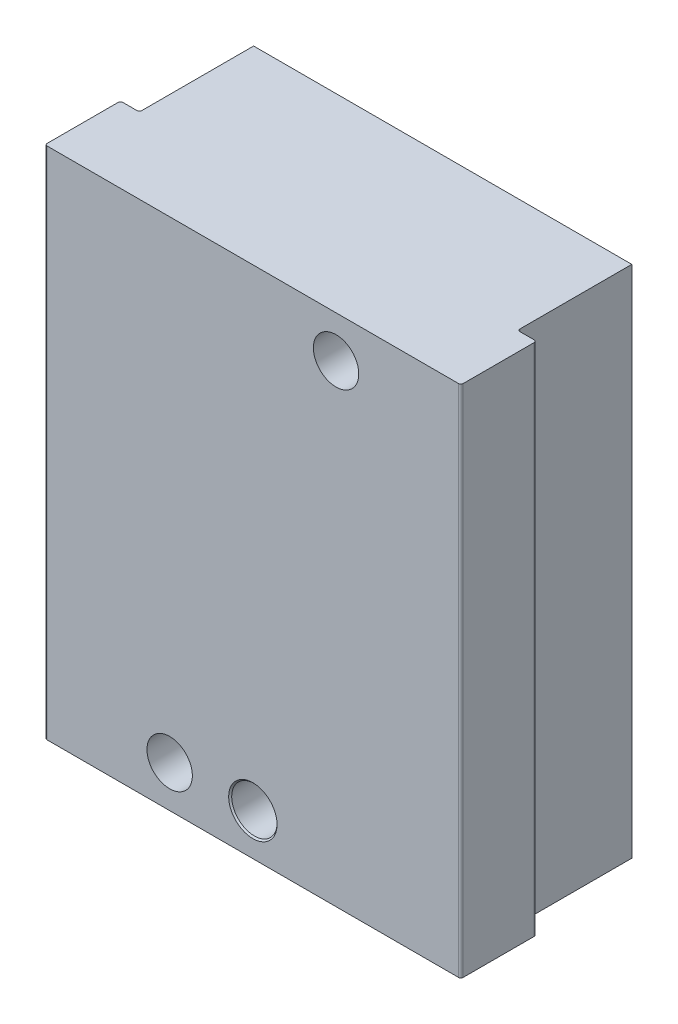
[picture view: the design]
ISO-10303-21;
HEADER;
FILE_DESCRIPTION(('STEP AP214'),'2;1');
FILE_NAME('part.step','',(''),(''),'','','');
FILE_SCHEMA(('AUTOMOTIVE_DESIGN { 1 0 10303 214 1 1 1 1 }'));
ENDSEC;
DATA;
#1=APPLICATION_CONTEXT('core data for automotive mechanical design processes');
#2=APPLICATION_PROTOCOL_DEFINITION('international standard','automotive_design',2000,#1);
#3=PRODUCT_CONTEXT('',#1,'mechanical');
#4=PRODUCT('Part','Part','',(#3));
#5=PRODUCT_RELATED_PRODUCT_CATEGORY('part','',(#4));
#6=PRODUCT_DEFINITION_FORMATION('','',#4);
#7=PRODUCT_DEFINITION_CONTEXT('part definition',#1,'design');
#8=PRODUCT_DEFINITION('design','',#6,#7);
#9=PRODUCT_DEFINITION_SHAPE('','',#8);
#10=(LENGTH_UNIT() NAMED_UNIT(*) SI_UNIT(.MILLI.,.METRE.));
#11=(NAMED_UNIT(*) PLANE_ANGLE_UNIT() SI_UNIT($,.RADIAN.));
#12=(NAMED_UNIT(*) SI_UNIT($,.STERADIAN.) SOLID_ANGLE_UNIT());
#13=UNCERTAINTY_MEASURE_WITH_UNIT(LENGTH_MEASURE(1.E-05),#10,'distance_accuracy_value','');
#14=(GEOMETRIC_REPRESENTATION_CONTEXT(3) GLOBAL_UNCERTAINTY_ASSIGNED_CONTEXT((#13)) GLOBAL_UNIT_ASSIGNED_CONTEXT((#10,
#11,#12)) REPRESENTATION_CONTEXT('',''));
#15=CARTESIAN_POINT('',(0.,0.,0.));
#16=DIRECTION('',(0.,0.,1.));
#17=DIRECTION('',(1.,0.,0.));
#18=AXIS2_PLACEMENT_3D('',#15,#16,#17);
#19=CARTESIAN_POINT('',(0.,5.5,0.));
#20=DIRECTION('',(0.,0.,-1.));
#21=DIRECTION('',(-1.,0.,0.));
#22=AXIS2_PLACEMENT_3D('',#19,#20,#21);
#23=CYLINDRICAL_SURFACE('',#22,1.5);
#24=CARTESIAN_POINT('',(0.,5.5,-25.1));
#25=DIRECTION('',(0.,0.,-1.));
#26=DIRECTION('',(-1.,0.,0.));
#27=AXIS2_PLACEMENT_3D('',#24,#25,#26);
#28=CIRCLE('',#27,1.5);
#29=CARTESIAN_POINT('',(0.70367829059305,4.17529744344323,-25.1));
#30=VERTEX_POINT('',#29);
#31=CARTESIAN_POINT('',(-0.70367829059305,6.82470255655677,-25.1));
#32=VERTEX_POINT('',#31);
#33=EDGE_CURVE('E509',#30,#32,#28,.T.);
#34=ORIENTED_EDGE('',*,*,#33,.T.);
#35=CARTESIAN_POINT('',(0.,5.5,-7.95492154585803));
#36=DIRECTION('',(-0.467333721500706,0.87977444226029,0.0871557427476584));
#37=DIRECTION('',(-0.0408864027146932,0.0769702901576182,-0.996194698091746));
#38=AXIS2_PLACEMENT_3D('',#35,#36,#37);
#39=ELLIPSE('',#38,17.2105698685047,1.5);
#40=CARTESIAN_POINT('',(0.168038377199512,6.99055798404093,-22.1));
#41=VERTEX_POINT('',#40);
#42=EDGE_CURVE('E714',#32,#41,#39,.F.);
#43=ORIENTED_EDGE('',*,*,#42,.T.);
#44=CARTESIAN_POINT('',(0.,5.5,-22.1));
#45=DIRECTION('',(0.,0.,-1.));
#46=DIRECTION('',(-1.,0.,0.));
#47=AXIS2_PLACEMENT_3D('',#44,#45,#46);
#48=CIRCLE('',#47,1.5);
#49=CARTESIAN_POINT('',(1.32913946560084,4.80473869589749,-22.1));
#50=VERTEX_POINT('',#49);
#51=EDGE_CURVE('E336',#50,#41,#48,.F.);
#52=ORIENTED_EDGE('',*,*,#51,.F.);
#53=CARTESIAN_POINT('',(0.,5.5,-7.95492154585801));
#54=DIRECTION('',(0.467333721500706,-0.87977444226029,0.0871557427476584));
#55=DIRECTION('',(0.0408864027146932,-0.0769702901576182,-0.996194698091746));
#56=AXIS2_PLACEMENT_3D('',#53,#54,#55);
#57=ELLIPSE('',#56,17.2105698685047,1.5);
#58=EDGE_CURVE('E715',#50,#30,#57,.F.);
#59=ORIENTED_EDGE('',*,*,#58,.T.);
#60=EDGE_LOOP('',(#34,#43,#52,#59));
#61=FACE_BOUND('',#60,.T.);
#62=CARTESIAN_POINT('',(0.,5.5,-10.));
#63=DIRECTION('',(0.,0.,1.));
#64=DIRECTION('',(1.,0.,0.));
#65=AXIS2_PLACEMENT_3D('',#62,#63,#64);
#66=CIRCLE('',#65,1.5);
#67=CARTESIAN_POINT('',(1.5,5.5,-10.));
#68=VERTEX_POINT('',#67);
#69=EDGE_CURVE('E506',#68,#68,#66,.F.);
#70=ORIENTED_EDGE('',*,*,#69,.F.);
#71=EDGE_LOOP('',(#70));
#72=FACE_BOUND('',#71,.T.);
#73=ADVANCED_FACE('F34',(#61,#72),#23,.F.);
#74=CARTESIAN_POINT('',(27.5,68.,-10.));
#75=DIRECTION('',(-1.,0.,0.));
#76=DIRECTION('',(0.,0.,1.));
#77=AXIS2_PLACEMENT_3D('',#74,#75,#76);
#78=PLANE('',#77);
#79=DIRECTION('',(0.,0.,-1.));
#80=VECTOR('',#79,1.);
#81=CARTESIAN_POINT('',(27.5,0.,-10.));
#82=LINE('',#81,#80);
#83=CARTESIAN_POINT('',(27.5,0.,-0.3));
#84=VERTEX_POINT('',#83);
#85=CARTESIAN_POINT('',(27.5,0.,-9.7));
#86=VERTEX_POINT('',#85);
#87=EDGE_CURVE('E604',#84,#86,#82,.T.);
#88=ORIENTED_EDGE('',*,*,#87,.T.);
#89=DIRECTION('',(0.,-1.,0.));
#90=VECTOR('',#89,1.);
#91=CARTESIAN_POINT('',(27.5,68.,-9.7));
#92=LINE('',#91,#90);
#93=CARTESIAN_POINT('',(27.5,68.,-9.7));
#94=VERTEX_POINT('',#93);
#95=EDGE_CURVE('E469',#86,#94,#92,.F.);
#96=ORIENTED_EDGE('',*,*,#95,.T.);
#97=DIRECTION('',(0.,0.,-1.));
#98=VECTOR('',#97,1.);
#99=CARTESIAN_POINT('',(27.5,68.,-10.));
#100=LINE('',#99,#98);
#101=CARTESIAN_POINT('',(27.5,68.,-0.3));
#102=VERTEX_POINT('',#101);
#103=EDGE_CURVE('E607',#102,#94,#100,.T.);
#104=ORIENTED_EDGE('',*,*,#103,.F.);
#105=DIRECTION('',(0.,-1.,0.));
#106=VECTOR('',#105,1.);
#107=CARTESIAN_POINT('',(27.5,68.,-0.3));
#108=LINE('',#107,#106);
#109=EDGE_CURVE('E473',#102,#84,#108,.T.);
#110=ORIENTED_EDGE('',*,*,#109,.T.);
#111=EDGE_LOOP('',(#88,#96,#104,#110));
#112=FACE_BOUND('',#111,.T.);
#113=ADVANCED_FACE('F377',(#112),#78,.F.);
#114=CARTESIAN_POINT('',(27.5,68.,-10.));
#115=DIRECTION('',(0.,0.,1.));
#116=DIRECTION('',(1.,0.,0.));
#117=AXIS2_PLACEMENT_3D('',#114,#115,#116);
#118=PLANE('',#117);
#119=DIRECTION('',(-1.,0.,0.));
#120=VECTOR('',#119,1.);
#121=CARTESIAN_POINT('',(27.5,68.,-10.));
#122=LINE('',#121,#120);
#123=CARTESIAN_POINT('',(27.2,68.,-10.));
#124=VERTEX_POINT('',#123);
#125=CARTESIAN_POINT('',(25.3,68.,-10.));
#126=VERTEX_POINT('',#125);
#127=EDGE_CURVE('E610',#124,#126,#122,.T.);
#128=ORIENTED_EDGE('',*,*,#127,.F.);
#129=DIRECTION('',(0.,-1.,0.));
#130=VECTOR('',#129,1.);
#131=CARTESIAN_POINT('',(27.2,68.,-10.));
#132=LINE('',#131,#130);
#133=CARTESIAN_POINT('',(27.2,0.,-10.));
#134=VERTEX_POINT('',#133);
#135=EDGE_CURVE('E656',#124,#134,#132,.T.);
#136=ORIENTED_EDGE('',*,*,#135,.T.);
#137=DIRECTION('',(-1.,0.,0.));
#138=VECTOR('',#137,1.);
#139=CARTESIAN_POINT('',(27.5,0.,-10.));
#140=LINE('',#139,#138);
#141=CARTESIAN_POINT('',(25.3,0.,-10.));
#142=VERTEX_POINT('',#141);
#143=EDGE_CURVE('E631',#134,#142,#140,.T.);
#144=ORIENTED_EDGE('',*,*,#143,.T.);
#145=DIRECTION('',(0.,-1.,0.));
#146=VECTOR('',#145,1.);
#147=CARTESIAN_POINT('',(25.3,68.,-10.));
#148=LINE('',#147,#146);
#149=EDGE_CURVE('E654',#142,#126,#148,.F.);
#150=ORIENTED_EDGE('',*,*,#149,.T.);
#151=EDGE_LOOP('',(#128,#136,#144,#150));
#152=FACE_BOUND('',#151,.T.);
#153=ADVANCED_FACE('F383',(#152),#118,.F.);
#154=CARTESIAN_POINT('',(25.,68.,-25.1));
#155=DIRECTION('',(-1.,0.,0.));
#156=DIRECTION('',(0.,0.,1.));
#157=AXIS2_PLACEMENT_3D('',#154,#155,#156);
#158=PLANE('',#157);
#159=DIRECTION('',(0.,0.,-1.));
#160=VECTOR('',#159,1.);
#161=CARTESIAN_POINT('',(25.,68.,-25.1));
#162=LINE('',#161,#160);
#163=CARTESIAN_POINT('',(25.,68.,-10.3));
#164=VERTEX_POINT('',#163);
#165=CARTESIAN_POINT('',(25.,68.,-25.1));
#166=VERTEX_POINT('',#165);
#167=EDGE_CURVE('E614',#164,#166,#162,.T.);
#168=ORIENTED_EDGE('',*,*,#167,.F.);
#169=DIRECTION('',(0.,-1.,0.));
#170=VECTOR('',#169,1.);
#171=CARTESIAN_POINT('',(25.,0.,-10.3));
#172=LINE('',#171,#170);
#173=CARTESIAN_POINT('',(25.,0.,-10.3));
#174=VERTEX_POINT('',#173);
#175=EDGE_CURVE('E480',#164,#174,#172,.T.);
#176=ORIENTED_EDGE('',*,*,#175,.T.);
#177=DIRECTION('',(0.,0.,-1.));
#178=VECTOR('',#177,1.);
#179=CARTESIAN_POINT('',(25.,0.,-25.1));
#180=LINE('',#179,#178);
#181=CARTESIAN_POINT('',(25.,0.,-25.1));
#182=VERTEX_POINT('',#181);
#183=EDGE_CURVE('E634',#174,#182,#180,.T.);
#184=ORIENTED_EDGE('',*,*,#183,.T.);
#185=DIRECTION('',(0.,-1.,0.));
#186=VECTOR('',#185,1.);
#187=CARTESIAN_POINT('',(25.,68.,-25.1));
#188=LINE('',#187,#186);
#189=EDGE_CURVE('E651',#166,#182,#188,.T.);
#190=ORIENTED_EDGE('',*,*,#189,.F.);
#191=EDGE_LOOP('',(#168,#176,#184,#190));
#192=FACE_BOUND('',#191,.T.);
#193=ADVANCED_FACE('F429',(#192),#158,.F.);
#194=CARTESIAN_POINT('',(-25.,68.,-25.1));
#195=DIRECTION('',(0.,0.,1.));
#196=DIRECTION('',(1.,0.,0.));
#197=AXIS2_PLACEMENT_3D('',#194,#195,#196);
#198=PLANE('',#197);
#199=DIRECTION('',(-0.469118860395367,0.883135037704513,0.));
#200=VECTOR('',#199,1.);
#201=CARTESIAN_POINT('',(-26.7317629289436,67.0800923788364,-25.1));
#202=LINE('',#201,#200);
#203=CARTESIAN_POINT('',(4.42894667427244,8.41880890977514,-25.1));
#204=VERTEX_POINT('',#203);
#205=CARTESIAN_POINT('',(3.71148847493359,9.76945269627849,-25.1));
#206=VERTEX_POINT('',#205);
#207=EDGE_CURVE('E334',#204,#206,#202,.T.);
#208=ORIENTED_EDGE('',*,*,#207,.F.);
#209=DIRECTION('',(0.883135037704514,0.469118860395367,0.));
#210=VECTOR('',#209,1.);
#211=CARTESIAN_POINT('',(4.8705141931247,8.65336833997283,-25.1));
#212=LINE('',#211,#210);
#213=CARTESIAN_POINT('',(3.91161814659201,8.14400544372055,-25.1));
#214=VERTEX_POINT('',#213);
#215=EDGE_CURVE('E326',#214,#204,#212,.T.);
#216=ORIENTED_EDGE('',*,*,#215,.F.);
#217=CARTESIAN_POINT('',(2.8972360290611,7.03900367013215,-25.1));
#218=DIRECTION('',(0.,0.,-1.));
#219=DIRECTION('',(-1.,0.,0.));
#220=AXIS2_PLACEMENT_3D('',#217,#218,#219);
#221=CIRCLE('',#220,1.5);
#222=CARTESIAN_POINT('',(2.19355773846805,8.36370622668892,-25.1));
#223=VERTEX_POINT('',#222);
#224=EDGE_CURVE('E723',#223,#214,#221,.T.);
#225=ORIENTED_EDGE('',*,*,#224,.F.);
#226=DIRECTION('',(0.883135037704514,0.469118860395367,0.));
#227=VECTOR('',#226,1.);
#228=CARTESIAN_POINT('',(2.19355773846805,8.36370622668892,-25.1));
#229=LINE('',#228,#227);
#230=EDGE_CURVE('E720',#32,#223,#229,.T.);
#231=ORIENTED_EDGE('',*,*,#230,.F.);
#232=ORIENTED_EDGE('',*,*,#33,.F.);
#233=DIRECTION('',(-0.883135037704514,-0.469118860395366,0.));
#234=VECTOR('',#233,1.);
#235=CARTESIAN_POINT('',(3.60091431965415,5.71430111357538,-25.1));
#236=LINE('',#235,#234);
#237=CARTESIAN_POINT('',(3.60091431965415,5.71430111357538,-25.1));
#238=VERTEX_POINT('',#237);
#239=EDGE_CURVE('E717',#238,#30,#236,.T.);
#240=ORIENTED_EDGE('',*,*,#239,.F.);
#241=CARTESIAN_POINT('',(4.38073700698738,7.26087040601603,-25.1));
#242=VERTEX_POINT('',#241);
#243=EDGE_CURVE('E62',#242,#238,#221,.T.);
#244=ORIENTED_EDGE('',*,*,#243,.F.);
#245=DIRECTION('',(-0.883135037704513,-0.469118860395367,0.));
#246=VECTOR('',#245,1.);
#247=CARTESIAN_POINT('',(5.33963305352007,7.77023330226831,-25.1));
#248=LINE('',#247,#246);
#249=CARTESIAN_POINT('',(4.89806553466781,7.53567387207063,-25.1));
#250=VERTEX_POINT('',#249);
#251=EDGE_CURVE('E311',#250,#242,#248,.T.);
#252=ORIENTED_EDGE('',*,*,#251,.F.);
#253=CARTESIAN_POINT('',(6.16552373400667,5.14963306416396,-25.1));
#254=VERTEX_POINT('',#253);
#255=EDGE_CURVE('E324',#254,#250,#202,.T.);
#256=ORIENTED_EDGE('',*,*,#255,.F.);
#257=CARTESIAN_POINT('',(7.97595056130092,6.11132672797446,-25.1));
#258=DIRECTION('',(0.,0.,1.));
#259=DIRECTION('',(1.,0.,0.));
#260=AXIS2_PLACEMENT_3D('',#257,#258,#259);
#261=CIRCLE('',#260,2.05);
#262=CARTESIAN_POINT('',(8.93764422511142,4.30089990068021,-25.1));
#263=VERTEX_POINT('',#262);
#264=EDGE_CURVE('E333',#254,#263,#261,.T.);
#265=ORIENTED_EDGE('',*,*,#264,.T.);
#266=DIRECTION('',(-0.883135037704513,-0.469118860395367,0.));
#267=VECTOR('',#266,1.);
#268=CARTESIAN_POINT('',(8.85898032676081,4.25911385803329,-25.1));
#269=LINE('',#268,#267);
#270=CARTESIAN_POINT('',(17.9897783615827,9.10936821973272,-25.1));
#271=VERTEX_POINT('',#270);
#272=EDGE_CURVE('E338',#271,#263,#269,.T.);
#273=ORIENTED_EDGE('',*,*,#272,.F.);
#274=CARTESIAN_POINT('',(17.0280846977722,10.919795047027,-25.1));
#275=DIRECTION('',(0.,0.,1.));
#276=DIRECTION('',(1.,0.,0.));
#277=AXIS2_PLACEMENT_3D('',#274,#275,#276);
#278=CIRCLE('',#277,2.05);
#279=CARTESIAN_POINT('',(18.8385115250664,11.8814887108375,-25.1));
#280=VERTEX_POINT('',#279);
#281=EDGE_CURVE('E552',#271,#280,#278,.T.);
#282=ORIENTED_EDGE('',*,*,#281,.T.);
#283=DIRECTION('',(0.469118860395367,-0.883135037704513,0.));
#284=VECTOR('',#283,1.);
#285=CARTESIAN_POINT('',(-14.0587751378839,73.8119480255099,-25.1));
#286=LINE('',#285,#284);
#287=CARTESIAN_POINT('',(16.3844762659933,16.501308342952,-25.1));
#288=VERTEX_POINT('',#287);
#289=EDGE_CURVE('E550',#288,#280,#286,.T.);
#290=ORIENTED_EDGE('',*,*,#289,.F.);
#291=CARTESIAN_POINT('',(14.5740494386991,15.5396146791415,-25.1));
#292=DIRECTION('',(0.,0.,1.));
#293=DIRECTION('',(1.,0.,0.));
#294=AXIS2_PLACEMENT_3D('',#291,#292,#293);
#295=CIRCLE('',#294,2.05);
#296=CARTESIAN_POINT('',(15.1545615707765,17.5057036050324,-25.1));
#297=VERTEX_POINT('',#296);
#298=EDGE_CURVE('E545',#288,#297,#295,.T.);
#299=ORIENTED_EDGE('',*,*,#298,.T.);
#300=CARTESIAN_POINT('',(17.4766100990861,25.3700593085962,-25.1));
#301=DIRECTION('',(0.,0.,1.));
#302=DIRECTION('',(1.,0.,0.));
#303=AXIS2_PLACEMENT_3D('',#300,#301,#302);
#304=CIRCLE('',#303,8.2);
#305=CARTESIAN_POINT('',(10.234902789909,21.5232846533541,-25.1));
#306=VERTEX_POINT('',#305);
#307=EDGE_CURVE('E539',#306,#297,#304,.T.);
#308=ORIENTED_EDGE('',*,*,#307,.F.);
#309=DIRECTION('',(0.469118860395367,-0.883135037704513,0.));
#310=VECTOR('',#309,1.);
#311=CARTESIAN_POINT('',(-16.7744153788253,72.3694075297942,-25.1));
#312=LINE('',#311,#310);
#313=CARTESIAN_POINT('',(-2.99319548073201,46.4257092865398,-25.1));
#314=VERTEX_POINT('',#313);
#315=EDGE_CURVE('E534',#314,#306,#312,.T.);
#316=ORIENTED_EDGE('',*,*,#315,.F.);
#317=CARTESIAN_POINT('',(4.248511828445,50.2724839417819,-25.1));
#318=DIRECTION('',(0.,0.,1.));
#319=DIRECTION('',(1.,0.,0.));
#320=AXIS2_PLACEMENT_3D('',#317,#318,#319);
#321=CIRCLE('',#320,8.2);
#322=CARTESIAN_POINT('',(-3.56782987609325,52.7513551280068,-25.1));
#323=VERTEX_POINT('',#322);
#324=EDGE_CURVE('E530',#323,#314,#321,.T.);
#325=ORIENTED_EDGE('',*,*,#324,.F.);
#326=CARTESIAN_POINT('',(-5.52191530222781,53.371072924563,-25.1));
#327=DIRECTION('',(0.,0.,1.));
#328=DIRECTION('',(1.,0.,0.));
#329=AXIS2_PLACEMENT_3D('',#326,#327,#328);
#330=CIRCLE('',#329,2.05);
#331=CARTESIAN_POINT('',(-3.71148847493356,54.3327665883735,-25.1));
#332=VERTEX_POINT('',#331);
#333=EDGE_CURVE('E524',#323,#332,#330,.T.);
#334=ORIENTED_EDGE('',*,*,#333,.T.);
#335=DIRECTION('',(0.469118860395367,-0.883135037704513,0.));
#336=VECTOR('',#335,1.);
#337=CARTESIAN_POINT('',(-14.0587751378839,73.8119480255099,-25.1));
#338=LINE('',#337,#336);
#339=CARTESIAN_POINT('',(-6.16552373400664,58.952586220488,-25.1));
#340=VERTEX_POINT('',#339);
#341=EDGE_CURVE('E522',#340,#332,#338,.T.);
#342=ORIENTED_EDGE('',*,*,#341,.F.);
#343=CARTESIAN_POINT('',(-7.9759505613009,57.9908925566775,-25.1));
#344=DIRECTION('',(0.,0.,1.));
#345=DIRECTION('',(1.,0.,0.));
#346=AXIS2_PLACEMENT_3D('',#343,#344,#345);
#347=CIRCLE('',#346,2.05);
#348=CARTESIAN_POINT('',(-8.9376442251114,59.8013193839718,-25.1));
#349=VERTEX_POINT('',#348);
#350=EDGE_CURVE('E516',#340,#349,#347,.T.);
#351=ORIENTED_EDGE('',*,*,#350,.T.);
#352=DIRECTION('',(0.883135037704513,0.469118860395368,0.));
#353=VECTOR('',#352,1.);
#354=CARTESIAN_POINT('',(-18.0684422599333,54.9510650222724,-25.1));
#355=LINE('',#354,#353);
#356=CARTESIAN_POINT('',(-17.9897783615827,54.9928510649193,-25.1));
#357=VERTEX_POINT('',#356);
#358=EDGE_CURVE('E519',#357,#349,#355,.T.);
#359=ORIENTED_EDGE('',*,*,#358,.F.);
#360=CARTESIAN_POINT('',(-17.0280846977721,53.182424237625,-25.1));
#361=DIRECTION('',(0.,0.,1.));
#362=DIRECTION('',(1.,0.,0.));
#363=AXIS2_PLACEMENT_3D('',#360,#361,#362);
#364=CIRCLE('',#363,2.05);
#365=CARTESIAN_POINT('',(-18.8385115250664,52.2207305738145,-25.1));
#366=VERTEX_POINT('',#365);
#367=EDGE_CURVE('E527',#357,#366,#364,.T.);
#368=ORIENTED_EDGE('',*,*,#367,.T.);
#369=DIRECTION('',(-0.469118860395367,0.883135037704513,0.));
#370=VECTOR('',#369,1.);
#371=CARTESIAN_POINT('',(-26.7317629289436,67.0800923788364,-25.1));
#372=LINE('',#371,#370);
#373=CARTESIAN_POINT('',(-16.3844762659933,47.6009109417,-25.1));
#374=VERTEX_POINT('',#373);
#375=EDGE_CURVE('E532',#374,#366,#372,.T.);
#376=ORIENTED_EDGE('',*,*,#375,.F.);
#377=CARTESIAN_POINT('',(-14.5740494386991,48.5626046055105,-25.1));
#378=DIRECTION('',(0.,0.,1.));
#379=DIRECTION('',(1.,0.,0.));
#380=AXIS2_PLACEMENT_3D('',#377,#378,#379);
#381=CIRCLE('',#380,2.05);
#382=CARTESIAN_POINT('',(-15.1545615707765,46.5965156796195,-25.1));
#383=VERTEX_POINT('',#382);
#384=EDGE_CURVE('E536',#374,#383,#381,.T.);
#385=ORIENTED_EDGE('',*,*,#384,.T.);
#386=CARTESIAN_POINT('',(-17.476610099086,38.7321599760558,-25.1));
#387=DIRECTION('',(0.,0.,1.));
#388=DIRECTION('',(1.,0.,0.));
#389=AXIS2_PLACEMENT_3D('',#386,#387,#388);
#390=CIRCLE('',#389,8.2);
#391=CARTESIAN_POINT('',(-10.234902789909,42.5789346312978,-25.1));
#392=VERTEX_POINT('',#391);
#393=EDGE_CURVE('E541',#392,#383,#390,.T.);
#394=ORIENTED_EDGE('',*,*,#393,.F.);
#395=DIRECTION('',(-0.469118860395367,0.883135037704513,0.));
#396=VECTOR('',#395,1.);
#397=CARTESIAN_POINT('',(-24.0161226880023,68.5226328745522,-25.1));
#398=LINE('',#397,#396);
#399=CARTESIAN_POINT('',(2.99319548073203,17.6765099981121,-25.1));
#400=VERTEX_POINT('',#399);
#401=EDGE_CURVE('E543',#400,#392,#398,.T.);
#402=ORIENTED_EDGE('',*,*,#401,.F.);
#403=CARTESIAN_POINT('',(-4.24851182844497,13.8297353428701,-25.1));
#404=DIRECTION('',(0.,0.,1.));
#405=DIRECTION('',(1.,0.,0.));
#406=AXIS2_PLACEMENT_3D('',#403,#404,#405);
#407=CIRCLE('',#406,8.2);
#408=CARTESIAN_POINT('',(3.56782987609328,11.3508641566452,-25.1));
#409=VERTEX_POINT('',#408);
#410=EDGE_CURVE('E548',#409,#400,#407,.T.);
#411=ORIENTED_EDGE('',*,*,#410,.F.);
#412=CARTESIAN_POINT('',(5.52191530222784,10.731146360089,-25.1));
#413=DIRECTION('',(0.,0.,1.));
#414=DIRECTION('',(1.,0.,0.));
#415=AXIS2_PLACEMENT_3D('',#412,#413,#414);
#416=CIRCLE('',#415,2.05);
#417=EDGE_CURVE('E554',#409,#206,#416,.T.);
#418=ORIENTED_EDGE('',*,*,#417,.T.);
#419=EDGE_LOOP('',(#208,#216,#225,#231,#232,#240,#244,#252,#256,#265,#273,#282,#290,#299,#308,
#316,#325,#334,#342,#351,#359,#368,#376,#385,#394,#402,#411,#418));
#420=FACE_BOUND('',#419,.T.);
#421=CARTESIAN_POINT('',(-11.,5.5,-25.1));
#422=DIRECTION('',(0.,0.,-1.));
#423=DIRECTION('',(-1.,0.,0.));
#424=AXIS2_PLACEMENT_3D('',#421,#422,#423);
#425=CIRCLE('',#424,3.);
#426=CARTESIAN_POINT('',(-14.,5.5,-25.1));
#427=VERTEX_POINT('',#426);
#428=EDGE_CURVE('E594',#427,#427,#425,.T.);
#429=ORIENTED_EDGE('',*,*,#428,.F.);
#430=EDGE_LOOP('',(#429));
#431=FACE_BOUND('',#430,.T.);
#432=CARTESIAN_POINT('',(11.,62.5,-25.1));
#433=DIRECTION('',(0.,0.,-1.));
#434=DIRECTION('',(-1.,0.,0.));
#435=AXIS2_PLACEMENT_3D('',#432,#433,#434);
#436=CIRCLE('',#435,3.);
#437=CARTESIAN_POINT('',(8.,62.5,-25.1));
#438=VERTEX_POINT('',#437);
#439=EDGE_CURVE('E598',#438,#438,#436,.T.);
#440=ORIENTED_EDGE('',*,*,#439,.F.);
#441=EDGE_LOOP('',(#440));
#442=FACE_BOUND('',#441,.T.);
#443=DIRECTION('',(-1.,0.,0.));
#444=VECTOR('',#443,1.);
#445=CARTESIAN_POINT('',(-25.,0.,-25.1));
#446=LINE('',#445,#444);
#447=CARTESIAN_POINT('',(-25.,0.,-25.1));
#448=VERTEX_POINT('',#447);
#449=EDGE_CURVE('E636',#182,#448,#446,.T.);
#450=ORIENTED_EDGE('',*,*,#449,.T.);
#451=DIRECTION('',(0.,-1.,0.));
#452=VECTOR('',#451,1.);
#453=CARTESIAN_POINT('',(-25.,68.,-25.1));
#454=LINE('',#453,#452);
#455=CARTESIAN_POINT('',(-25.,68.,-25.1));
#456=VERTEX_POINT('',#455);
#457=EDGE_CURVE('E628',#456,#448,#454,.T.);
#458=ORIENTED_EDGE('',*,*,#457,.F.);
#459=DIRECTION('',(-1.,0.,0.));
#460=VECTOR('',#459,1.);
#461=CARTESIAN_POINT('',(-25.,68.,-25.1));
#462=LINE('',#461,#460);
#463=EDGE_CURVE('E616',#166,#456,#462,.T.);
#464=ORIENTED_EDGE('',*,*,#463,.F.);
#465=ORIENTED_EDGE('',*,*,#189,.T.);
#466=EDGE_LOOP('',(#450,#458,#464,#465));
#467=FACE_BOUND('',#466,.T.);
#468=ADVANCED_FACE('F321',(#420,#431,#442,#467),#198,.F.);
#469=CARTESIAN_POINT('',(-25.,68.,-25.1));
#470=DIRECTION('',(1.,0.,0.));
#471=DIRECTION('',(0.,0.,-1.));
#472=AXIS2_PLACEMENT_3D('',#469,#470,#471);
#473=PLANE('',#472);
#474=DIRECTION('',(0.,0.,1.));
#475=VECTOR('',#474,1.);
#476=CARTESIAN_POINT('',(-25.,0.,-25.1));
#477=LINE('',#476,#475);
#478=CARTESIAN_POINT('',(-25.,0.,-10.3));
#479=VERTEX_POINT('',#478);
#480=EDGE_CURVE('E638',#448,#479,#477,.T.);
#481=ORIENTED_EDGE('',*,*,#480,.T.);
#482=DIRECTION('',(0.,-1.,0.));
#483=VECTOR('',#482,1.);
#484=CARTESIAN_POINT('',(-25.,68.,-10.3));
#485=LINE('',#484,#483);
#486=CARTESIAN_POINT('',(-25.,68.,-10.3));
#487=VERTEX_POINT('',#486);
#488=EDGE_CURVE('E488',#479,#487,#485,.F.);
#489=ORIENTED_EDGE('',*,*,#488,.T.);
#490=DIRECTION('',(0.,0.,1.));
#491=VECTOR('',#490,1.);
#492=CARTESIAN_POINT('',(-25.,68.,-25.1));
#493=LINE('',#492,#491);
#494=EDGE_CURVE('E618',#456,#487,#493,.T.);
#495=ORIENTED_EDGE('',*,*,#494,.F.);
#496=ORIENTED_EDGE('',*,*,#457,.T.);
#497=EDGE_LOOP('',(#481,#489,#495,#496));
#498=FACE_BOUND('',#497,.T.);
#499=ADVANCED_FACE('F422',(#498),#473,.F.);
#500=CARTESIAN_POINT('',(-27.5,68.,-10.));
#501=DIRECTION('',(0.,0.,1.));
#502=DIRECTION('',(1.,0.,0.));
#503=AXIS2_PLACEMENT_3D('',#500,#501,#502);
#504=PLANE('',#503);
#505=DIRECTION('',(-1.,0.,0.));
#506=VECTOR('',#505,1.);
#507=CARTESIAN_POINT('',(-27.5,68.,-10.));
#508=LINE('',#507,#506);
#509=CARTESIAN_POINT('',(-25.3,68.,-10.));
#510=VERTEX_POINT('',#509);
#511=CARTESIAN_POINT('',(-27.2,68.,-10.));
#512=VERTEX_POINT('',#511);
#513=EDGE_CURVE('E621',#510,#512,#508,.T.);
#514=ORIENTED_EDGE('',*,*,#513,.F.);
#515=DIRECTION('',(0.,-1.,0.));
#516=VECTOR('',#515,1.);
#517=CARTESIAN_POINT('',(-25.3,0.,-10.));
#518=LINE('',#517,#516);
#519=CARTESIAN_POINT('',(-25.3,0.,-10.));
#520=VERTEX_POINT('',#519);
#521=EDGE_CURVE('E485',#510,#520,#518,.T.);
#522=ORIENTED_EDGE('',*,*,#521,.T.);
#523=DIRECTION('',(-1.,0.,0.));
#524=VECTOR('',#523,1.);
#525=CARTESIAN_POINT('',(-27.5,0.,-10.));
#526=LINE('',#525,#524);
#527=CARTESIAN_POINT('',(-27.2,0.,-10.));
#528=VERTEX_POINT('',#527);
#529=EDGE_CURVE('E641',#520,#528,#526,.T.);
#530=ORIENTED_EDGE('',*,*,#529,.T.);
#531=DIRECTION('',(0.,-1.,0.));
#532=VECTOR('',#531,1.);
#533=CARTESIAN_POINT('',(-27.2,68.,-10.));
#534=LINE('',#533,#532);
#535=EDGE_CURVE('E483',#528,#512,#534,.F.);
#536=ORIENTED_EDGE('',*,*,#535,.T.);
#537=EDGE_LOOP('',(#514,#522,#530,#536));
#538=FACE_BOUND('',#537,.T.);
#539=ADVANCED_FACE('F418',(#538),#504,.F.);
#540=CARTESIAN_POINT('',(-27.5,68.,-10.));
#541=DIRECTION('',(1.,0.,0.));
#542=DIRECTION('',(0.,0.,-1.));
#543=AXIS2_PLACEMENT_3D('',#540,#541,#542);
#544=PLANE('',#543);
#545=DIRECTION('',(0.,0.,1.));
#546=VECTOR('',#545,1.);
#547=CARTESIAN_POINT('',(-27.5,68.,-10.));
#548=LINE('',#547,#546);
#549=CARTESIAN_POINT('',(-27.5,68.,-9.7));
#550=VERTEX_POINT('',#549);
#551=CARTESIAN_POINT('',(-27.5,68.,-0.3));
#552=VERTEX_POINT('',#551);
#553=EDGE_CURVE('E624',#550,#552,#548,.T.);
#554=ORIENTED_EDGE('',*,*,#553,.F.);
#555=DIRECTION('',(0.,-1.,0.));
#556=VECTOR('',#555,1.);
#557=CARTESIAN_POINT('',(-27.5,68.,-9.7));
#558=LINE('',#557,#556);
#559=CARTESIAN_POINT('',(-27.5,0.,-9.7));
#560=VERTEX_POINT('',#559);
#561=EDGE_CURVE('E491',#550,#560,#558,.T.);
#562=ORIENTED_EDGE('',*,*,#561,.T.);
#563=DIRECTION('',(0.,0.,1.));
#564=VECTOR('',#563,1.);
#565=CARTESIAN_POINT('',(-27.5,0.,-10.));
#566=LINE('',#565,#564);
#567=CARTESIAN_POINT('',(-27.5,0.,-0.3));
#568=VERTEX_POINT('',#567);
#569=EDGE_CURVE('E644',#560,#568,#566,.T.);
#570=ORIENTED_EDGE('',*,*,#569,.T.);
#571=DIRECTION('',(0.,-1.,0.));
#572=VECTOR('',#571,1.);
#573=CARTESIAN_POINT('',(-27.5,68.,-0.3));
#574=LINE('',#573,#572);
#575=EDGE_CURVE('E462',#568,#552,#574,.F.);
#576=ORIENTED_EDGE('',*,*,#575,.T.);
#577=EDGE_LOOP('',(#554,#562,#570,#576));
#578=FACE_BOUND('',#577,.T.);
#579=ADVANCED_FACE('F414',(#578),#544,.F.);
#580=CARTESIAN_POINT('',(-27.5,68.,0.));
#581=DIRECTION('',(0.,0.,-1.));
#582=DIRECTION('',(-1.,0.,0.));
#583=AXIS2_PLACEMENT_3D('',#580,#581,#582);
#584=PLANE('',#583);
#585=CARTESIAN_POINT('',(0.,5.5,0.));
#586=DIRECTION('',(0.,0.,-1.));
#587=DIRECTION('',(-1.,0.,0.));
#588=AXIS2_PLACEMENT_3D('',#585,#586,#587);
#589=CIRCLE('',#588,3.2);
#590=CARTESIAN_POINT('',(-3.2,5.5,0.));
#591=VERTEX_POINT('',#590);
#592=EDGE_CURVE('E513',#591,#591,#589,.T.);
#593=ORIENTED_EDGE('',*,*,#592,.T.);
#594=EDGE_LOOP('',(#593));
#595=FACE_BOUND('',#594,.T.);
#596=CARTESIAN_POINT('',(-11.,5.5,0.));
#597=DIRECTION('',(0.,0.,-1.));
#598=DIRECTION('',(-1.,0.,0.));
#599=AXIS2_PLACEMENT_3D('',#596,#597,#598);
#600=CIRCLE('',#599,3.);
#601=CARTESIAN_POINT('',(-14.,5.5,0.));
#602=VERTEX_POINT('',#601);
#603=EDGE_CURVE('E595',#602,#602,#600,.T.);
#604=ORIENTED_EDGE('',*,*,#603,.T.);
#605=EDGE_LOOP('',(#604));
#606=FACE_BOUND('',#605,.T.);
#607=CARTESIAN_POINT('',(11.,62.5,0.));
#608=DIRECTION('',(0.,0.,-1.));
#609=DIRECTION('',(-1.,0.,0.));
#610=AXIS2_PLACEMENT_3D('',#607,#608,#609);
#611=CIRCLE('',#610,3.);
#612=CARTESIAN_POINT('',(8.,62.5,0.));
#613=VERTEX_POINT('',#612);
#614=EDGE_CURVE('E601',#613,#613,#611,.T.);
#615=ORIENTED_EDGE('',*,*,#614,.T.);
#616=EDGE_LOOP('',(#615));
#617=FACE_BOUND('',#616,.T.);
#618=DIRECTION('',(1.,0.,0.));
#619=VECTOR('',#618,1.);
#620=CARTESIAN_POINT('',(-27.5,0.,0.));
#621=LINE('',#620,#619);
#622=CARTESIAN_POINT('',(-27.2,0.,0.));
#623=VERTEX_POINT('',#622);
#624=CARTESIAN_POINT('',(27.2,0.,0.));
#625=VERTEX_POINT('',#624);
#626=EDGE_CURVE('E611',#623,#625,#621,.T.);
#627=ORIENTED_EDGE('',*,*,#626,.T.);
#628=DIRECTION('',(0.,-1.,0.));
#629=VECTOR('',#628,1.);
#630=CARTESIAN_POINT('',(27.2,68.,0.));
#631=LINE('',#630,#629);
#632=CARTESIAN_POINT('',(27.2,68.,0.));
#633=VERTEX_POINT('',#632);
#634=EDGE_CURVE('E495',#625,#633,#631,.F.);
#635=ORIENTED_EDGE('',*,*,#634,.T.);
#636=DIRECTION('',(1.,0.,0.));
#637=VECTOR('',#636,1.);
#638=CARTESIAN_POINT('',(-27.5,68.,0.));
#639=LINE('',#638,#637);
#640=CARTESIAN_POINT('',(-27.2,68.,0.));
#641=VERTEX_POINT('',#640);
#642=EDGE_CURVE('E626',#641,#633,#639,.T.);
#643=ORIENTED_EDGE('',*,*,#642,.F.);
#644=DIRECTION('',(0.,-1.,0.));
#645=VECTOR('',#644,1.);
#646=CARTESIAN_POINT('',(-27.2,68.,0.));
#647=LINE('',#646,#645);
#648=EDGE_CURVE('E464',#641,#623,#647,.T.);
#649=ORIENTED_EDGE('',*,*,#648,.T.);
#650=EDGE_LOOP('',(#627,#635,#643,#649));
#651=FACE_BOUND('',#650,.T.);
#652=ADVANCED_FACE('F406',(#595,#606,#617,#651),#584,.F.);
#653=CARTESIAN_POINT('',(0.,68.,0.));
#654=DIRECTION('',(0.,1.,0.));
#655=DIRECTION('',(0.,0.,1.));
#656=AXIS2_PLACEMENT_3D('',#653,#654,#655);
#657=PLANE('',#656);
#658=ORIENTED_EDGE('',*,*,#103,.T.);
#659=CARTESIAN_POINT('',(27.2,68.,-9.7));
#660=DIRECTION('',(0.,1.,0.));
#661=DIRECTION('',(0.,0.,1.));
#662=AXIS2_PLACEMENT_3D('',#659,#660,#661);
#663=CIRCLE('',#662,0.3);
#664=EDGE_CURVE('E478',#94,#124,#663,.T.);
#665=ORIENTED_EDGE('',*,*,#664,.T.);
#666=ORIENTED_EDGE('',*,*,#127,.T.);
#667=CARTESIAN_POINT('',(25.3,68.,-10.3));
#668=DIRECTION('',(0.,1.,0.));
#669=DIRECTION('',(0.,0.,1.));
#670=AXIS2_PLACEMENT_3D('',#667,#668,#669);
#671=CIRCLE('',#670,0.3);
#672=EDGE_CURVE('E499',#126,#164,#671,.F.);
#673=ORIENTED_EDGE('',*,*,#672,.T.);
#674=ORIENTED_EDGE('',*,*,#167,.T.);
#675=ORIENTED_EDGE('',*,*,#463,.T.);
#676=ORIENTED_EDGE('',*,*,#494,.T.);
#677=CARTESIAN_POINT('',(-25.3,68.,-10.3));
#678=DIRECTION('',(0.,1.,0.));
#679=DIRECTION('',(0.,0.,1.));
#680=AXIS2_PLACEMENT_3D('',#677,#678,#679);
#681=CIRCLE('',#680,0.3);
#682=EDGE_CURVE('E503',#487,#510,#681,.F.);
#683=ORIENTED_EDGE('',*,*,#682,.T.);
#684=ORIENTED_EDGE('',*,*,#513,.T.);
#685=CARTESIAN_POINT('',(-27.2,68.,-9.7));
#686=DIRECTION('',(0.,1.,0.));
#687=DIRECTION('',(0.,0.,1.));
#688=AXIS2_PLACEMENT_3D('',#685,#686,#687);
#689=CIRCLE('',#688,0.3);
#690=EDGE_CURVE('E471',#512,#550,#689,.T.);
#691=ORIENTED_EDGE('',*,*,#690,.T.);
#692=ORIENTED_EDGE('',*,*,#553,.T.);
#693=CARTESIAN_POINT('',(-27.2,68.,-0.3));
#694=DIRECTION('',(0.,1.,0.));
#695=DIRECTION('',(0.,0.,1.));
#696=AXIS2_PLACEMENT_3D('',#693,#694,#695);
#697=CIRCLE('',#696,0.3);
#698=EDGE_CURVE('E461',#552,#641,#697,.T.);
#699=ORIENTED_EDGE('',*,*,#698,.T.);
#700=ORIENTED_EDGE('',*,*,#642,.T.);
#701=CARTESIAN_POINT('',(27.2,68.,-0.3));
#702=DIRECTION('',(0.,1.,0.));
#703=DIRECTION('',(0.,0.,1.));
#704=AXIS2_PLACEMENT_3D('',#701,#702,#703);
#705=CIRCLE('',#704,0.3);
#706=EDGE_CURVE('E468',#633,#102,#705,.T.);
#707=ORIENTED_EDGE('',*,*,#706,.T.);
#708=EDGE_LOOP('',(#658,#665,#666,#673,#674,#675,#676,#683,#684,#691,#692,#699,#700,#707));
#709=FACE_BOUND('',#708,.T.);
#710=ADVANCED_FACE('F402',(#709),#657,.T.);
#711=CARTESIAN_POINT('',(0.,0.,0.));
#712=DIRECTION('',(0.,1.,0.));
#713=DIRECTION('',(0.,0.,1.));
#714=AXIS2_PLACEMENT_3D('',#711,#712,#713);
#715=PLANE('',#714);
#716=ORIENTED_EDGE('',*,*,#143,.F.);
#717=CARTESIAN_POINT('',(27.2,0.,-9.7));
#718=DIRECTION('',(0.,1.,0.));
#719=DIRECTION('',(0.,0.,1.));
#720=AXIS2_PLACEMENT_3D('',#717,#718,#719);
#721=CIRCLE('',#720,0.3);
#722=EDGE_CURVE('E665',#134,#86,#721,.F.);
#723=ORIENTED_EDGE('',*,*,#722,.T.);
#724=ORIENTED_EDGE('',*,*,#87,.F.);
#725=CARTESIAN_POINT('',(27.2,0.,-0.3));
#726=DIRECTION('',(0.,1.,0.));
#727=DIRECTION('',(0.,0.,1.));
#728=AXIS2_PLACEMENT_3D('',#725,#726,#727);
#729=CIRCLE('',#728,0.3);
#730=EDGE_CURVE('E661',#84,#625,#729,.F.);
#731=ORIENTED_EDGE('',*,*,#730,.T.);
#732=ORIENTED_EDGE('',*,*,#626,.F.);
#733=CARTESIAN_POINT('',(-27.2,0.,-0.3));
#734=DIRECTION('',(0.,1.,0.));
#735=DIRECTION('',(0.,0.,1.));
#736=AXIS2_PLACEMENT_3D('',#733,#734,#735);
#737=CIRCLE('',#736,0.3);
#738=EDGE_CURVE('E659',#623,#568,#737,.F.);
#739=ORIENTED_EDGE('',*,*,#738,.T.);
#740=ORIENTED_EDGE('',*,*,#569,.F.);
#741=CARTESIAN_POINT('',(-27.2,0.,-9.7));
#742=DIRECTION('',(0.,1.,0.));
#743=DIRECTION('',(0.,0.,1.));
#744=AXIS2_PLACEMENT_3D('',#741,#742,#743);
#745=CIRCLE('',#744,0.3);
#746=EDGE_CURVE('E663',#560,#528,#745,.F.);
#747=ORIENTED_EDGE('',*,*,#746,.T.);
#748=ORIENTED_EDGE('',*,*,#529,.F.);
#749=CARTESIAN_POINT('',(-25.3,0.,-10.3));
#750=DIRECTION('',(0.,1.,0.));
#751=DIRECTION('',(0.,0.,1.));
#752=AXIS2_PLACEMENT_3D('',#749,#750,#751);
#753=CIRCLE('',#752,0.3);
#754=EDGE_CURVE('E501',#520,#479,#753,.T.);
#755=ORIENTED_EDGE('',*,*,#754,.T.);
#756=ORIENTED_EDGE('',*,*,#480,.F.);
#757=ORIENTED_EDGE('',*,*,#449,.F.);
#758=ORIENTED_EDGE('',*,*,#183,.F.);
#759=CARTESIAN_POINT('',(25.3,0.,-10.3));
#760=DIRECTION('',(0.,1.,0.));
#761=DIRECTION('',(0.,0.,1.));
#762=AXIS2_PLACEMENT_3D('',#759,#760,#761);
#763=CIRCLE('',#762,0.3);
#764=EDGE_CURVE('E497',#174,#142,#763,.T.);
#765=ORIENTED_EDGE('',*,*,#764,.T.);
#766=EDGE_LOOP('',(#716,#723,#724,#731,#732,#739,#740,#747,#748,#755,#756,#757,#758,#765));
#767=FACE_BOUND('',#766,.T.);
#768=ADVANCED_FACE('F405',(#767),#715,.F.);
#769=CARTESIAN_POINT('',(27.2,68.,-9.7));
#770=DIRECTION('',(0.,-1.,0.));
#771=DIRECTION('',(0.,0.,-1.));
#772=AXIS2_PLACEMENT_3D('',#769,#770,#771);
#773=CYLINDRICAL_SURFACE('',#772,0.3);
#774=ORIENTED_EDGE('',*,*,#664,.F.);
#775=ORIENTED_EDGE('',*,*,#95,.F.);
#776=ORIENTED_EDGE('',*,*,#722,.F.);
#777=ORIENTED_EDGE('',*,*,#135,.F.);
#778=EDGE_LOOP('',(#774,#775,#776,#777));
#779=FACE_BOUND('',#778,.T.);
#780=ADVANCED_FACE('F410',(#779),#773,.T.);
#781=CARTESIAN_POINT('',(25.3,68.,-10.3));
#782=DIRECTION('',(0.,1.,0.));
#783=DIRECTION('',(0.,0.,1.));
#784=AXIS2_PLACEMENT_3D('',#781,#782,#783);
#785=CYLINDRICAL_SURFACE('',#784,0.3);
#786=ORIENTED_EDGE('',*,*,#672,.F.);
#787=ORIENTED_EDGE('',*,*,#149,.F.);
#788=ORIENTED_EDGE('',*,*,#764,.F.);
#789=ORIENTED_EDGE('',*,*,#175,.F.);
#790=EDGE_LOOP('',(#786,#787,#788,#789));
#791=FACE_BOUND('',#790,.T.);
#792=ADVANCED_FACE('F438',(#791),#785,.F.);
#793=CARTESIAN_POINT('',(-25.3,68.,-10.3));
#794=DIRECTION('',(0.,1.,0.));
#795=DIRECTION('',(0.,0.,1.));
#796=AXIS2_PLACEMENT_3D('',#793,#794,#795);
#797=CYLINDRICAL_SURFACE('',#796,0.3);
#798=ORIENTED_EDGE('',*,*,#682,.F.);
#799=ORIENTED_EDGE('',*,*,#488,.F.);
#800=ORIENTED_EDGE('',*,*,#754,.F.);
#801=ORIENTED_EDGE('',*,*,#521,.F.);
#802=EDGE_LOOP('',(#798,#799,#800,#801));
#803=FACE_BOUND('',#802,.T.);
#804=ADVANCED_FACE('F442',(#803),#797,.F.);
#805=CARTESIAN_POINT('',(-27.2,68.,-9.7));
#806=DIRECTION('',(0.,-1.,0.));
#807=DIRECTION('',(0.,0.,-1.));
#808=AXIS2_PLACEMENT_3D('',#805,#806,#807);
#809=CYLINDRICAL_SURFACE('',#808,0.3);
#810=ORIENTED_EDGE('',*,*,#690,.F.);
#811=ORIENTED_EDGE('',*,*,#535,.F.);
#812=ORIENTED_EDGE('',*,*,#746,.F.);
#813=ORIENTED_EDGE('',*,*,#561,.F.);
#814=EDGE_LOOP('',(#810,#811,#812,#813));
#815=FACE_BOUND('',#814,.T.);
#816=ADVANCED_FACE('F446',(#815),#809,.T.);
#817=CARTESIAN_POINT('',(27.2,68.,-0.3));
#818=DIRECTION('',(0.,-1.,0.));
#819=DIRECTION('',(0.,0.,-1.));
#820=AXIS2_PLACEMENT_3D('',#817,#818,#819);
#821=CYLINDRICAL_SURFACE('',#820,0.3);
#822=ORIENTED_EDGE('',*,*,#706,.F.);
#823=ORIENTED_EDGE('',*,*,#634,.F.);
#824=ORIENTED_EDGE('',*,*,#730,.F.);
#825=ORIENTED_EDGE('',*,*,#109,.F.);
#826=EDGE_LOOP('',(#822,#823,#824,#825));
#827=FACE_BOUND('',#826,.T.);
#828=ADVANCED_FACE('F450',(#827),#821,.T.);
#829=CARTESIAN_POINT('',(-27.2,68.,-0.3));
#830=DIRECTION('',(0.,-1.,0.));
#831=DIRECTION('',(0.,0.,-1.));
#832=AXIS2_PLACEMENT_3D('',#829,#830,#831);
#833=CYLINDRICAL_SURFACE('',#832,0.3);
#834=ORIENTED_EDGE('',*,*,#698,.F.);
#835=ORIENTED_EDGE('',*,*,#575,.F.);
#836=ORIENTED_EDGE('',*,*,#738,.F.);
#837=ORIENTED_EDGE('',*,*,#648,.F.);
#838=EDGE_LOOP('',(#834,#835,#836,#837));
#839=FACE_BOUND('',#838,.T.);
#840=ADVANCED_FACE('F400',(#839),#833,.T.);
#841=CARTESIAN_POINT('',(11.,62.5,0.));
#842=DIRECTION('',(0.,0.,-1.));
#843=DIRECTION('',(-1.,0.,0.));
#844=AXIS2_PLACEMENT_3D('',#841,#842,#843);
#845=CYLINDRICAL_SURFACE('',#844,3.);
#846=ORIENTED_EDGE('',*,*,#614,.F.);
#847=EDGE_LOOP('',(#846));
#848=FACE_BOUND('',#847,.T.);
#849=ORIENTED_EDGE('',*,*,#439,.T.);
#850=EDGE_LOOP('',(#849));
#851=FACE_BOUND('',#850,.T.);
#852=ADVANCED_FACE('F396',(#848,#851),#845,.F.);
#853=CARTESIAN_POINT('',(-11.,5.5,0.));
#854=DIRECTION('',(0.,0.,-1.));
#855=DIRECTION('',(-1.,0.,0.));
#856=AXIS2_PLACEMENT_3D('',#853,#854,#855);
#857=CYLINDRICAL_SURFACE('',#856,3.);
#858=ORIENTED_EDGE('',*,*,#603,.F.);
#859=EDGE_LOOP('',(#858));
#860=FACE_BOUND('',#859,.T.);
#861=ORIENTED_EDGE('',*,*,#428,.T.);
#862=EDGE_LOOP('',(#861));
#863=FACE_BOUND('',#862,.T.);
#864=ADVANCED_FACE('F392',(#860,#863),#857,.F.);
#865=CARTESIAN_POINT('',(0.,5.5,-10.));
#866=DIRECTION('',(0.,0.,1.));
#867=DIRECTION('',(1.,0.,0.));
#868=AXIS2_PLACEMENT_3D('',#865,#866,#867);
#869=PLANE('',#868);
#870=CARTESIAN_POINT('',(0.,5.5,-10.));
#871=DIRECTION('',(0.,0.,1.));
#872=DIRECTION('',(1.,0.,0.));
#873=AXIS2_PLACEMENT_3D('',#870,#871,#872);
#874=CIRCLE('',#873,3.);
#875=CARTESIAN_POINT('',(3.,5.5,-10.));
#876=VERTEX_POINT('',#875);
#877=EDGE_CURVE('E510',#876,#876,#874,.T.);
#878=ORIENTED_EDGE('',*,*,#877,.T.);
#879=EDGE_LOOP('',(#878));
#880=FACE_BOUND('',#879,.T.);
#881=ORIENTED_EDGE('',*,*,#69,.T.);
#882=EDGE_LOOP('',(#881));
#883=FACE_BOUND('',#882,.T.);
#884=ADVANCED_FACE('F395',(#880,#883),#869,.T.);
#885=CARTESIAN_POINT('',(0.,5.5,-10.));
#886=DIRECTION('',(0.,0.,1.));
#887=DIRECTION('',(1.,0.,0.));
#888=AXIS2_PLACEMENT_3D('',#885,#886,#887);
#889=CYLINDRICAL_SURFACE('',#888,3.);
#890=CARTESIAN_POINT('',(0.,5.5,-0.200000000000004));
#891=DIRECTION('',(0.,0.,-1.));
#892=DIRECTION('',(-1.,0.,0.));
#893=AXIS2_PLACEMENT_3D('',#890,#891,#892);
#894=CIRCLE('',#893,3.);
#895=CARTESIAN_POINT('',(-3.,5.5,-0.200000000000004));
#896=VERTEX_POINT('',#895);
#897=EDGE_CURVE('E505',#896,#896,#894,.F.);
#898=ORIENTED_EDGE('',*,*,#897,.T.);
#899=EDGE_LOOP('',(#898));
#900=FACE_BOUND('',#899,.T.);
#901=ORIENTED_EDGE('',*,*,#877,.F.);
#902=EDGE_LOOP('',(#901));
#903=FACE_BOUND('',#902,.T.);
#904=ADVANCED_FACE('F390',(#900,#903),#889,.F.);
#905=CARTESIAN_POINT('',(0.,5.5,-0.200000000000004));
#906=DIRECTION('',(0.,0.,1.));
#907=DIRECTION('',(1.,0.,0.));
#908=AXIS2_PLACEMENT_3D('',#905,#906,#907);
#909=CONICAL_SURFACE('',#908,3.,0.785398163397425);
#910=ORIENTED_EDGE('',*,*,#592,.F.);
#911=EDGE_LOOP('',(#910));
#912=FACE_BOUND('',#911,.T.);
#913=ORIENTED_EDGE('',*,*,#897,.F.);
#914=EDGE_LOOP('',(#913));
#915=FACE_BOUND('',#914,.T.);
#916=ADVANCED_FACE('F36',(#912,#915),#909,.F.);
#917=CARTESIAN_POINT('',(-13.2377902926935,48.2319905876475,-23.58125));
#918=DIRECTION('',(0.883135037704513,0.469118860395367,0.));
#919=DIRECTION('',(0.,0.,-1.));
#920=AXIS2_PLACEMENT_3D('',#917,#918,#919);
#921=PLANE('',#920);
#922=ORIENTED_EDGE('',*,*,#401,.T.);
#923=DIRECTION('',(0.,0.,-1.));
#924=VECTOR('',#923,1.);
#925=CARTESIAN_POINT('',(-10.234902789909,42.5789346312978,-23.58125));
#926=LINE('',#925,#924);
#927=CARTESIAN_POINT('',(-10.234902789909,42.5789346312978,-23.58125));
#928=VERTEX_POINT('',#927);
#929=EDGE_CURVE('E767',#928,#392,#926,.T.);
#930=ORIENTED_EDGE('',*,*,#929,.F.);
#931=DIRECTION('',(0.469118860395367,-0.883135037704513,0.));
#932=VECTOR('',#931,1.);
#933=CARTESIAN_POINT('',(-13.2377902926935,48.2319905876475,-23.58125));
#934=LINE('',#933,#932);
#935=CARTESIAN_POINT('',(2.99319548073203,17.6765099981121,-23.58125));
#936=VERTEX_POINT('',#935);
#937=EDGE_CURVE('E743',#928,#936,#934,.T.);
#938=ORIENTED_EDGE('',*,*,#937,.T.);
#939=DIRECTION('',(0.,0.,1.));
#940=VECTOR('',#939,1.);
#941=CARTESIAN_POINT('',(2.99319548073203,17.6765099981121,-23.58125));
#942=LINE('',#941,#940);
#943=EDGE_CURVE('E765',#400,#936,#942,.T.);
#944=ORIENTED_EDGE('',*,*,#943,.F.);
#945=EDGE_LOOP('',(#922,#930,#938,#944));
#946=FACE_BOUND('',#945,.T.);
#947=ADVANCED_FACE('F1058',(#946),#921,.T.);
#948=CARTESIAN_POINT('',(3.28044274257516,10.5809135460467,-23.58125));
#949=DIRECTION('',(0.883135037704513,0.469118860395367,0.));
#950=DIRECTION('',(0.,0.,-1.));
#951=AXIS2_PLACEMENT_3D('',#948,#949,#950);
#952=PLANE('',#951);
#953=DIRECTION('',(0.0163720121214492,-0.0308209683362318,0.999390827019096));
#954=VECTOR('',#953,1.);
#955=CARTESIAN_POINT('',(4.45239767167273,8.3746614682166,-23.668489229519));
#956=LINE('',#955,#954);
#957=CARTESIAN_POINT('',(4.43713767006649,8.40338903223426,-24.6));
#958=VERTEX_POINT('',#957);
#959=EDGE_CURVE('E315',#204,#958,#956,.T.);
#960=ORIENTED_EDGE('',*,*,#959,.F.);
#961=ORIENTED_EDGE('',*,*,#207,.T.);
#962=DIRECTION('',(0.,0.,1.));
#963=VECTOR('',#962,1.);
#964=CARTESIAN_POINT('',(3.71148847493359,9.76945269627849,-23.58125));
#965=LINE('',#964,#963);
#966=CARTESIAN_POINT('',(3.71148847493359,9.76945269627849,-23.58125));
#967=VERTEX_POINT('',#966);
#968=EDGE_CURVE('E813',#967,#206,#965,.F.);
#969=ORIENTED_EDGE('',*,*,#968,.F.);
#970=DIRECTION('',(0.469118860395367,-0.883135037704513,0.));
#971=VECTOR('',#970,1.);
#972=CARTESIAN_POINT('',(3.28044274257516,10.5809135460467,-23.58125));
#973=LINE('',#972,#971);
#974=CARTESIAN_POINT('',(6.16552373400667,5.14963306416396,-23.58125));
#975=VERTEX_POINT('',#974);
#976=EDGE_CURVE('E746',#967,#975,#973,.T.);
#977=ORIENTED_EDGE('',*,*,#976,.T.);
#978=DIRECTION('',(0.,0.,-1.));
#979=VECTOR('',#978,1.);
#980=CARTESIAN_POINT('',(6.16552373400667,5.14963306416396,-23.58125));
#981=LINE('',#980,#979);
#982=EDGE_CURVE('E332',#254,#975,#981,.F.);
#983=ORIENTED_EDGE('',*,*,#982,.F.);
#984=ORIENTED_EDGE('',*,*,#255,.T.);
#985=DIRECTION('',(0.0163720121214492,-0.0308209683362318,-0.999390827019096));
#986=VECTOR('',#985,1.);
#987=CARTESIAN_POINT('',(4.87124546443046,7.58616372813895,-23.4628321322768));
#988=LINE('',#987,#986);
#989=CARTESIAN_POINT('',(4.88987453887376,7.55109374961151,-24.6));
#990=VERTEX_POINT('',#989);
#991=EDGE_CURVE('E308',#990,#250,#988,.T.);
#992=ORIENTED_EDGE('',*,*,#991,.F.);
#993=DIRECTION('',(0.469118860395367,-0.883135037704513,0.));
#994=VECTOR('',#993,1.);
#995=CARTESIAN_POINT('',(3.28044274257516,10.5809135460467,-24.6));
#996=LINE('',#995,#994);
#997=EDGE_CURVE('E316',#958,#990,#996,.T.);
#998=ORIENTED_EDGE('',*,*,#997,.F.);
#999=EDGE_LOOP('',(#960,#961,#969,#977,#983,#984,#992,#998));
#1000=FACE_BOUND('',#999,.T.);
#1001=ADVANCED_FACE('F330',(#1000),#952,.T.);
#1002=CARTESIAN_POINT('',(7.12721739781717,3.33920623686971,-23.58125));
#1003=DIRECTION('',(-0.469118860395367,0.883135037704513,0.));
#1004=DIRECTION('',(0.,0.,1.));
#1005=AXIS2_PLACEMENT_3D('',#1002,#1003,#1004);
#1006=PLANE('',#1005);
#1007=ORIENTED_EDGE('',*,*,#272,.T.);
#1008=DIRECTION('',(0.,0.,-1.));
#1009=VECTOR('',#1008,1.);
#1010=CARTESIAN_POINT('',(8.93764422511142,4.30089990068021,-23.58125));
#1011=LINE('',#1010,#1009);
#1012=CARTESIAN_POINT('',(8.93764422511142,4.30089990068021,-23.58125));
#1013=VERTEX_POINT('',#1012);
#1014=EDGE_CURVE('E564',#1013,#263,#1011,.T.);
#1015=ORIENTED_EDGE('',*,*,#1014,.F.);
#1016=DIRECTION('',(0.883135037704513,0.469118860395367,0.));
#1017=VECTOR('',#1016,1.);
#1018=CARTESIAN_POINT('',(7.12721739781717,3.33920623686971,-23.58125));
#1019=LINE('',#1018,#1017);
#1020=CARTESIAN_POINT('',(17.9897783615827,9.10936821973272,-23.58125));
#1021=VERTEX_POINT('',#1020);
#1022=EDGE_CURVE('E748',#1013,#1021,#1019,.T.);
#1023=ORIENTED_EDGE('',*,*,#1022,.T.);
#1024=DIRECTION('',(0.,0.,-1.));
#1025=VECTOR('',#1024,1.);
#1026=CARTESIAN_POINT('',(17.9897783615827,9.10936821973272,-23.58125));
#1027=LINE('',#1026,#1025);
#1028=EDGE_CURVE('E565',#271,#1021,#1027,.F.);
#1029=ORIENTED_EDGE('',*,*,#1028,.F.);
#1030=EDGE_LOOP('',(#1007,#1015,#1023,#1029));
#1031=FACE_BOUND('',#1030,.T.);
#1032=ADVANCED_FACE('F562',(#1031),#1006,.T.);
#1033=CARTESIAN_POINT('',(15.9534305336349,17.3127691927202,-23.58125));
#1034=DIRECTION('',(-0.883135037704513,-0.469118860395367,0.));
#1035=DIRECTION('',(0.469118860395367,-0.883135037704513,0.));
#1036=AXIS2_PLACEMENT_3D('',#1033,#1034,#1035);
#1037=PLANE('',#1036);
#1038=ORIENTED_EDGE('',*,*,#289,.T.);
#1039=DIRECTION('',(0.,0.,-1.));
#1040=VECTOR('',#1039,1.);
#1041=CARTESIAN_POINT('',(18.8385115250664,11.8814887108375,-23.58125));
#1042=LINE('',#1041,#1040);
#1043=CARTESIAN_POINT('',(18.8385115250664,11.8814887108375,-23.58125));
#1044=VERTEX_POINT('',#1043);
#1045=EDGE_CURVE('E573',#1044,#280,#1042,.T.);
#1046=ORIENTED_EDGE('',*,*,#1045,.F.);
#1047=DIRECTION('',(-0.469118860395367,0.883135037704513,0.));
#1048=VECTOR('',#1047,1.);
#1049=CARTESIAN_POINT('',(15.9534305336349,17.3127691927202,-23.58125));
#1050=LINE('',#1049,#1048);
#1051=CARTESIAN_POINT('',(16.3844762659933,16.501308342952,-23.58125));
#1052=VERTEX_POINT('',#1051);
#1053=EDGE_CURVE('E750',#1044,#1052,#1050,.T.);
#1054=ORIENTED_EDGE('',*,*,#1053,.T.);
#1055=DIRECTION('',(0.,0.,-1.));
#1056=VECTOR('',#1055,1.);
#1057=CARTESIAN_POINT('',(16.3844762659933,16.501308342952,-23.58125));
#1058=LINE('',#1057,#1056);
#1059=EDGE_CURVE('E571',#288,#1052,#1058,.F.);
#1060=ORIENTED_EDGE('',*,*,#1059,.F.);
#1061=EDGE_LOOP('',(#1038,#1046,#1054,#1060));
#1062=FACE_BOUND('',#1061,.T.);
#1063=ADVANCED_FACE('F1033',(#1062),#1037,.T.);
#1064=CARTESIAN_POINT('',(-5.99608298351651,52.0787652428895,-23.58125));
#1065=DIRECTION('',(-0.883135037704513,-0.469118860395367,0.));
#1066=DIRECTION('',(0.469118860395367,-0.883135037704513,0.));
#1067=AXIS2_PLACEMENT_3D('',#1064,#1065,#1066);
#1068=PLANE('',#1067);
#1069=ORIENTED_EDGE('',*,*,#315,.T.);
#1070=DIRECTION('',(0.,0.,-1.));
#1071=VECTOR('',#1070,1.);
#1072=CARTESIAN_POINT('',(10.234902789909,21.5232846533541,-23.58125));
#1073=LINE('',#1072,#1071);
#1074=CARTESIAN_POINT('',(10.234902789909,21.5232846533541,-23.58125));
#1075=VERTEX_POINT('',#1074);
#1076=EDGE_CURVE('E770',#1075,#306,#1073,.T.);
#1077=ORIENTED_EDGE('',*,*,#1076,.F.);
#1078=DIRECTION('',(-0.469118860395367,0.883135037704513,0.));
#1079=VECTOR('',#1078,1.);
#1080=CARTESIAN_POINT('',(-5.99608298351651,52.0787652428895,-23.58125));
#1081=LINE('',#1080,#1079);
#1082=CARTESIAN_POINT('',(-2.99319548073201,46.4257092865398,-23.58125));
#1083=VERTEX_POINT('',#1082);
#1084=EDGE_CURVE('E753',#1075,#1083,#1081,.T.);
#1085=ORIENTED_EDGE('',*,*,#1084,.T.);
#1086=DIRECTION('',(0.,0.,1.));
#1087=VECTOR('',#1086,1.);
#1088=CARTESIAN_POINT('',(-2.99319548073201,46.4257092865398,-23.58125));
#1089=LINE('',#1088,#1087);
#1090=EDGE_CURVE('E773',#314,#1083,#1089,.T.);
#1091=ORIENTED_EDGE('',*,*,#1090,.F.);
#1092=EDGE_LOOP('',(#1069,#1077,#1085,#1091));
#1093=FACE_BOUND('',#1092,.T.);
#1094=ADVANCED_FACE('F1023',(#1093),#1068,.T.);
#1095=CARTESIAN_POINT('',(-7.12721739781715,60.7630130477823,-23.58125));
#1096=DIRECTION('',(-0.883135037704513,-0.469118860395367,0.));
#1097=DIRECTION('',(0.469118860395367,-0.883135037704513,0.));
#1098=AXIS2_PLACEMENT_3D('',#1095,#1096,#1097);
#1099=PLANE('',#1098);
#1100=ORIENTED_EDGE('',*,*,#341,.T.);
#1101=DIRECTION('',(0.,0.,1.));
#1102=VECTOR('',#1101,1.);
#1103=CARTESIAN_POINT('',(-3.71148847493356,54.3327665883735,-23.58125));
#1104=LINE('',#1103,#1102);
#1105=CARTESIAN_POINT('',(-3.71148847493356,54.3327665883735,-23.58125));
#1106=VERTEX_POINT('',#1105);
#1107=EDGE_CURVE('E586',#1106,#332,#1104,.F.);
#1108=ORIENTED_EDGE('',*,*,#1107,.F.);
#1109=DIRECTION('',(-0.469118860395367,0.883135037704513,0.));
#1110=VECTOR('',#1109,1.);
#1111=CARTESIAN_POINT('',(-7.12721739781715,60.7630130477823,-23.58125));
#1112=LINE('',#1111,#1110);
#1113=CARTESIAN_POINT('',(-6.16552373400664,58.952586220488,-23.58125));
#1114=VERTEX_POINT('',#1113);
#1115=EDGE_CURVE('E756',#1106,#1114,#1112,.T.);
#1116=ORIENTED_EDGE('',*,*,#1115,.T.);
#1117=DIRECTION('',(0.,0.,-1.));
#1118=VECTOR('',#1117,1.);
#1119=CARTESIAN_POINT('',(-6.16552373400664,58.952586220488,-23.58125));
#1120=LINE('',#1119,#1118);
#1121=EDGE_CURVE('E584',#340,#1114,#1120,.F.);
#1122=ORIENTED_EDGE('',*,*,#1121,.F.);
#1123=EDGE_LOOP('',(#1100,#1108,#1116,#1122));
#1124=FACE_BOUND('',#1123,.T.);
#1125=ADVANCED_FACE('F1013',(#1124),#1099,.T.);
#1126=CARTESIAN_POINT('',(-19.8002051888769,54.0311574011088,-23.58125));
#1127=DIRECTION('',(0.469118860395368,-0.883135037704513,0.));
#1128=DIRECTION('',(0.883135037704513,0.469118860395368,0.));
#1129=AXIS2_PLACEMENT_3D('',#1126,#1127,#1128);
#1130=PLANE('',#1129);
#1131=ORIENTED_EDGE('',*,*,#358,.T.);
#1132=DIRECTION('',(0.,0.,-1.));
#1133=VECTOR('',#1132,1.);
#1134=CARTESIAN_POINT('',(-8.9376442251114,59.8013193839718,-23.58125));
#1135=LINE('',#1134,#1133);
#1136=CARTESIAN_POINT('',(-8.9376442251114,59.8013193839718,-23.58125));
#1137=VERTEX_POINT('',#1136);
#1138=EDGE_CURVE('E790',#1137,#349,#1135,.T.);
#1139=ORIENTED_EDGE('',*,*,#1138,.F.);
#1140=DIRECTION('',(-0.883135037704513,-0.469118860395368,0.));
#1141=VECTOR('',#1140,1.);
#1142=CARTESIAN_POINT('',(-19.8002051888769,54.0311574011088,-23.58125));
#1143=LINE('',#1142,#1141);
#1144=CARTESIAN_POINT('',(-17.9897783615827,54.9928510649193,-23.58125));
#1145=VERTEX_POINT('',#1144);
#1146=EDGE_CURVE('E759',#1137,#1145,#1143,.T.);
#1147=ORIENTED_EDGE('',*,*,#1146,.T.);
#1148=DIRECTION('',(0.,0.,-1.));
#1149=VECTOR('',#1148,1.);
#1150=CARTESIAN_POINT('',(-17.9897783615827,54.9928510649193,-23.58125));
#1151=LINE('',#1150,#1149);
#1152=EDGE_CURVE('E792',#357,#1145,#1151,.F.);
#1153=ORIENTED_EDGE('',*,*,#1152,.F.);
#1154=EDGE_LOOP('',(#1131,#1139,#1147,#1153));
#1155=FACE_BOUND('',#1154,.T.);
#1156=ADVANCED_FACE('F1003',(#1155),#1130,.T.);
#1157=CARTESIAN_POINT('',(-19.8002051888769,54.0311574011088,-23.58125));
#1158=DIRECTION('',(0.883135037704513,0.469118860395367,0.));
#1159=DIRECTION('',(0.,0.,-1.));
#1160=AXIS2_PLACEMENT_3D('',#1157,#1158,#1159);
#1161=PLANE('',#1160);
#1162=ORIENTED_EDGE('',*,*,#375,.T.);
#1163=DIRECTION('',(0.,0.,-1.));
#1164=VECTOR('',#1163,1.);
#1165=CARTESIAN_POINT('',(-18.8385115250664,52.2207305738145,-23.58125));
#1166=LINE('',#1165,#1164);
#1167=CARTESIAN_POINT('',(-18.8385115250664,52.2207305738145,-23.58125));
#1168=VERTEX_POINT('',#1167);
#1169=EDGE_CURVE('E787',#1168,#366,#1166,.T.);
#1170=ORIENTED_EDGE('',*,*,#1169,.F.);
#1171=DIRECTION('',(0.469118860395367,-0.883135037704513,0.));
#1172=VECTOR('',#1171,1.);
#1173=CARTESIAN_POINT('',(-19.8002051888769,54.0311574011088,-23.58125));
#1174=LINE('',#1173,#1172);
#1175=CARTESIAN_POINT('',(-16.3844762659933,47.6009109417,-23.58125));
#1176=VERTEX_POINT('',#1175);
#1177=EDGE_CURVE('E762',#1168,#1176,#1174,.T.);
#1178=ORIENTED_EDGE('',*,*,#1177,.T.);
#1179=DIRECTION('',(0.,0.,-1.));
#1180=VECTOR('',#1179,1.);
#1181=CARTESIAN_POINT('',(-16.3844762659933,47.6009109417,-23.58125));
#1182=LINE('',#1181,#1180);
#1183=EDGE_CURVE('E785',#374,#1176,#1182,.F.);
#1184=ORIENTED_EDGE('',*,*,#1183,.F.);
#1185=EDGE_LOOP('',(#1162,#1170,#1178,#1184));
#1186=FACE_BOUND('',#1185,.T.);
#1187=ADVANCED_FACE('F993',(#1186),#1161,.T.);
#1188=CARTESIAN_POINT('',(-17.476610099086,38.7321599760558,-23.58125));
#1189=DIRECTION('',(0.,0.,-1.));
#1190=DIRECTION('',(-0.883135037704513,-0.469118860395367,0.));
#1191=AXIS2_PLACEMENT_3D('',#1188,#1189,#1190);
#1192=CYLINDRICAL_SURFACE('',#1191,8.2);
#1193=ORIENTED_EDGE('',*,*,#393,.T.);
#1194=DIRECTION('',(0.,0.,-1.));
#1195=VECTOR('',#1194,1.);
#1196=CARTESIAN_POINT('',(-15.1545615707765,46.5965156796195,-23.58125));
#1197=LINE('',#1196,#1195);
#1198=CARTESIAN_POINT('',(-15.1545615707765,46.5965156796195,-23.58125));
#1199=VERTEX_POINT('',#1198);
#1200=EDGE_CURVE('E809',#1199,#383,#1197,.T.);
#1201=ORIENTED_EDGE('',*,*,#1200,.F.);
#1202=CARTESIAN_POINT('',(-17.476610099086,38.7321599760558,-23.58125));
#1203=DIRECTION('',(0.,0.,-1.));
#1204=DIRECTION('',(-0.883135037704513,-0.469118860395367,0.));
#1205=AXIS2_PLACEMENT_3D('',#1202,#1203,#1204);
#1206=CIRCLE('',#1205,8.2);
#1207=EDGE_CURVE('E775',#1199,#928,#1206,.T.);
#1208=ORIENTED_EDGE('',*,*,#1207,.T.);
#1209=ORIENTED_EDGE('',*,*,#929,.T.);
#1210=EDGE_LOOP('',(#1193,#1201,#1208,#1209));
#1211=FACE_BOUND('',#1210,.T.);
#1212=ADVANCED_FACE('F983',(#1211),#1192,.T.);
#1213=CARTESIAN_POINT('',(4.248511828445,50.2724839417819,-23.58125));
#1214=DIRECTION('',(0.,0.,1.));
#1215=DIRECTION('',(0.883135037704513,0.469118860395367,0.));
#1216=AXIS2_PLACEMENT_3D('',#1213,#1214,#1215);
#1217=CYLINDRICAL_SURFACE('',#1216,8.2);
#1218=ORIENTED_EDGE('',*,*,#324,.T.);
#1219=ORIENTED_EDGE('',*,*,#1090,.T.);
#1220=CARTESIAN_POINT('',(4.248511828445,50.2724839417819,-23.58125));
#1221=DIRECTION('',(0.,0.,-1.));
#1222=DIRECTION('',(-0.883135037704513,-0.469118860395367,0.));
#1223=AXIS2_PLACEMENT_3D('',#1220,#1221,#1222);
#1224=CIRCLE('',#1223,8.2);
#1225=CARTESIAN_POINT('',(-3.56782987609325,52.7513551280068,-23.58125));
#1226=VERTEX_POINT('',#1225);
#1227=EDGE_CURVE('E777',#1083,#1226,#1224,.T.);
#1228=ORIENTED_EDGE('',*,*,#1227,.T.);
#1229=DIRECTION('',(0.,0.,1.));
#1230=VECTOR('',#1229,1.);
#1231=CARTESIAN_POINT('',(-3.56782987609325,52.7513551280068,-23.58125));
#1232=LINE('',#1231,#1230);
#1233=EDGE_CURVE('E589',#323,#1226,#1232,.T.);
#1234=ORIENTED_EDGE('',*,*,#1233,.F.);
#1235=EDGE_LOOP('',(#1218,#1219,#1228,#1234));
#1236=FACE_BOUND('',#1235,.T.);
#1237=ADVANCED_FACE('F973',(#1236),#1217,.T.);
#1238=CARTESIAN_POINT('',(17.4766100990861,25.3700593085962,-23.58125));
#1239=DIRECTION('',(0.,0.,-1.));
#1240=DIRECTION('',(-0.883135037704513,-0.469118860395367,0.));
#1241=AXIS2_PLACEMENT_3D('',#1238,#1239,#1240);
#1242=CYLINDRICAL_SURFACE('',#1241,8.2);
#1243=ORIENTED_EDGE('',*,*,#307,.T.);
#1244=DIRECTION('',(0.,0.,-1.));
#1245=VECTOR('',#1244,1.);
#1246=CARTESIAN_POINT('',(15.1545615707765,17.5057036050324,-23.58125));
#1247=LINE('',#1246,#1245);
#1248=CARTESIAN_POINT('',(15.1545615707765,17.5057036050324,-23.58125));
#1249=VERTEX_POINT('',#1248);
#1250=EDGE_CURVE('E581',#1249,#297,#1247,.T.);
#1251=ORIENTED_EDGE('',*,*,#1250,.F.);
#1252=CARTESIAN_POINT('',(17.4766100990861,25.3700593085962,-23.58125));
#1253=DIRECTION('',(0.,0.,-1.));
#1254=DIRECTION('',(-0.883135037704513,-0.469118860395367,0.));
#1255=AXIS2_PLACEMENT_3D('',#1252,#1253,#1254);
#1256=CIRCLE('',#1255,8.2);
#1257=EDGE_CURVE('E780',#1249,#1075,#1256,.T.);
#1258=ORIENTED_EDGE('',*,*,#1257,.T.);
#1259=ORIENTED_EDGE('',*,*,#1076,.T.);
#1260=EDGE_LOOP('',(#1243,#1251,#1258,#1259));
#1261=FACE_BOUND('',#1260,.T.);
#1262=ADVANCED_FACE('F964',(#1261),#1242,.T.);
#1263=CARTESIAN_POINT('',(-4.24851182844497,13.8297353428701,-23.58125));
#1264=DIRECTION('',(0.,0.,1.));
#1265=DIRECTION('',(0.883135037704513,0.469118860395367,0.));
#1266=AXIS2_PLACEMENT_3D('',#1263,#1264,#1265);
#1267=CYLINDRICAL_SURFACE('',#1266,8.2);
#1268=ORIENTED_EDGE('',*,*,#410,.T.);
#1269=ORIENTED_EDGE('',*,*,#943,.T.);
#1270=CARTESIAN_POINT('',(-4.24851182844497,13.8297353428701,-23.58125));
#1271=DIRECTION('',(0.,0.,-1.));
#1272=DIRECTION('',(-0.883135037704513,-0.469118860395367,0.));
#1273=AXIS2_PLACEMENT_3D('',#1270,#1271,#1272);
#1274=CIRCLE('',#1273,8.2);
#1275=CARTESIAN_POINT('',(3.56782987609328,11.3508641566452,-23.58125));
#1276=VERTEX_POINT('',#1275);
#1277=EDGE_CURVE('E782',#936,#1276,#1274,.T.);
#1278=ORIENTED_EDGE('',*,*,#1277,.T.);
#1279=DIRECTION('',(0.,0.,1.));
#1280=VECTOR('',#1279,1.);
#1281=CARTESIAN_POINT('',(3.56782987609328,11.3508641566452,-23.58125));
#1282=LINE('',#1281,#1280);
#1283=EDGE_CURVE('E575',#409,#1276,#1282,.T.);
#1284=ORIENTED_EDGE('',*,*,#1283,.F.);
#1285=EDGE_LOOP('',(#1268,#1269,#1278,#1284));
#1286=FACE_BOUND('',#1285,.T.);
#1287=ADVANCED_FACE('F822',(#1286),#1267,.T.);
#1288=CARTESIAN_POINT('',(-17.0280846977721,53.182424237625,-23.58125));
#1289=DIRECTION('',(0.,0.,-1.));
#1290=DIRECTION('',(-0.883135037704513,-0.469118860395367,0.));
#1291=AXIS2_PLACEMENT_3D('',#1288,#1289,#1290);
#1292=CYLINDRICAL_SURFACE('',#1291,2.05);
#1293=ORIENTED_EDGE('',*,*,#1152,.T.);
#1294=CARTESIAN_POINT('',(-17.0280846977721,53.182424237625,-23.58125));
#1295=DIRECTION('',(0.,0.,-1.));
#1296=DIRECTION('',(-0.883135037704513,-0.469118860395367,0.));
#1297=AXIS2_PLACEMENT_3D('',#1294,#1295,#1296);
#1298=CIRCLE('',#1297,2.05);
#1299=EDGE_CURVE('E807',#1145,#1168,#1298,.F.);
#1300=ORIENTED_EDGE('',*,*,#1299,.T.);
#1301=ORIENTED_EDGE('',*,*,#1169,.T.);
#1302=ORIENTED_EDGE('',*,*,#367,.F.);
#1303=EDGE_LOOP('',(#1293,#1300,#1301,#1302));
#1304=FACE_BOUND('',#1303,.T.);
#1305=ADVANCED_FACE('F945',(#1304),#1292,.F.);
#1306=CARTESIAN_POINT('',(-14.5740494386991,48.5626046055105,-23.58125));
#1307=DIRECTION('',(0.,0.,-1.));
#1308=DIRECTION('',(-0.883135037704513,-0.469118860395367,0.));
#1309=AXIS2_PLACEMENT_3D('',#1306,#1307,#1308);
#1310=CYLINDRICAL_SURFACE('',#1309,2.05);
#1311=ORIENTED_EDGE('',*,*,#1183,.T.);
#1312=CARTESIAN_POINT('',(-14.5740494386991,48.5626046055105,-23.58125));
#1313=DIRECTION('',(0.,0.,-1.));
#1314=DIRECTION('',(-0.883135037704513,-0.469118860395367,0.));
#1315=AXIS2_PLACEMENT_3D('',#1312,#1313,#1314);
#1316=CIRCLE('',#1315,2.05);
#1317=EDGE_CURVE('E805',#1176,#1199,#1316,.F.);
#1318=ORIENTED_EDGE('',*,*,#1317,.T.);
#1319=ORIENTED_EDGE('',*,*,#1200,.T.);
#1320=ORIENTED_EDGE('',*,*,#384,.F.);
#1321=EDGE_LOOP('',(#1311,#1318,#1319,#1320));
#1322=FACE_BOUND('',#1321,.T.);
#1323=ADVANCED_FACE('F936',(#1322),#1310,.F.);
#1324=CARTESIAN_POINT('',(5.52191530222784,10.731146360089,-23.58125));
#1325=DIRECTION('',(0.,0.,1.));
#1326=DIRECTION('',(0.883135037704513,0.469118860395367,0.));
#1327=AXIS2_PLACEMENT_3D('',#1324,#1325,#1326);
#1328=CYLINDRICAL_SURFACE('',#1327,2.05);
#1329=ORIENTED_EDGE('',*,*,#1283,.T.);
#1330=CARTESIAN_POINT('',(5.52191530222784,10.731146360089,-23.58125));
#1331=DIRECTION('',(0.,0.,-1.));
#1332=DIRECTION('',(-0.883135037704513,-0.469118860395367,0.));
#1333=AXIS2_PLACEMENT_3D('',#1330,#1331,#1332);
#1334=CIRCLE('',#1333,2.05);
#1335=EDGE_CURVE('E803',#1276,#967,#1334,.F.);
#1336=ORIENTED_EDGE('',*,*,#1335,.T.);
#1337=ORIENTED_EDGE('',*,*,#968,.T.);
#1338=ORIENTED_EDGE('',*,*,#417,.F.);
#1339=EDGE_LOOP('',(#1329,#1336,#1337,#1338));
#1340=FACE_BOUND('',#1339,.T.);
#1341=ADVANCED_FACE('F817',(#1340),#1328,.F.);
#1342=CARTESIAN_POINT('',(7.97595056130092,6.11132672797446,-23.58125));
#1343=DIRECTION('',(0.,0.,-1.));
#1344=DIRECTION('',(-0.883135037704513,-0.469118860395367,0.));
#1345=AXIS2_PLACEMENT_3D('',#1342,#1343,#1344);
#1346=CYLINDRICAL_SURFACE('',#1345,2.05);
#1347=ORIENTED_EDGE('',*,*,#982,.T.);
#1348=CARTESIAN_POINT('',(7.97595056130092,6.11132672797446,-23.58125));
#1349=DIRECTION('',(0.,0.,-1.));
#1350=DIRECTION('',(-0.883135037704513,-0.469118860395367,0.));
#1351=AXIS2_PLACEMENT_3D('',#1348,#1349,#1350);
#1352=CIRCLE('',#1351,2.05);
#1353=EDGE_CURVE('E569',#975,#1013,#1352,.F.);
#1354=ORIENTED_EDGE('',*,*,#1353,.T.);
#1355=ORIENTED_EDGE('',*,*,#1014,.T.);
#1356=ORIENTED_EDGE('',*,*,#264,.F.);
#1357=EDGE_LOOP('',(#1347,#1354,#1355,#1356));
#1358=FACE_BOUND('',#1357,.T.);
#1359=ADVANCED_FACE('F567',(#1358),#1346,.F.);
#1360=CARTESIAN_POINT('',(17.0280846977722,10.919795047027,-23.58125));
#1361=DIRECTION('',(0.,0.,-1.));
#1362=DIRECTION('',(-0.883135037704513,-0.469118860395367,0.));
#1363=AXIS2_PLACEMENT_3D('',#1360,#1361,#1362);
#1364=CYLINDRICAL_SURFACE('',#1363,2.05);
#1365=ORIENTED_EDGE('',*,*,#1028,.T.);
#1366=CARTESIAN_POINT('',(17.0280846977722,10.919795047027,-23.58125));
#1367=DIRECTION('',(0.,0.,-1.));
#1368=DIRECTION('',(-0.883135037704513,-0.469118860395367,0.));
#1369=AXIS2_PLACEMENT_3D('',#1366,#1367,#1368);
#1370=CIRCLE('',#1369,2.05);
#1371=EDGE_CURVE('E800',#1021,#1044,#1370,.F.);
#1372=ORIENTED_EDGE('',*,*,#1371,.T.);
#1373=ORIENTED_EDGE('',*,*,#1045,.T.);
#1374=ORIENTED_EDGE('',*,*,#281,.F.);
#1375=EDGE_LOOP('',(#1365,#1372,#1373,#1374));
#1376=FACE_BOUND('',#1375,.T.);
#1377=ADVANCED_FACE('F909',(#1376),#1364,.F.);
#1378=CARTESIAN_POINT('',(14.5740494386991,15.5396146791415,-23.58125));
#1379=DIRECTION('',(0.,0.,-1.));
#1380=DIRECTION('',(-0.883135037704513,-0.469118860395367,0.));
#1381=AXIS2_PLACEMENT_3D('',#1378,#1379,#1380);
#1382=CYLINDRICAL_SURFACE('',#1381,2.05);
#1383=ORIENTED_EDGE('',*,*,#1059,.T.);
#1384=CARTESIAN_POINT('',(14.5740494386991,15.5396146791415,-23.58125));
#1385=DIRECTION('',(0.,0.,-1.));
#1386=DIRECTION('',(-0.883135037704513,-0.469118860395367,0.));
#1387=AXIS2_PLACEMENT_3D('',#1384,#1385,#1386);
#1388=CIRCLE('',#1387,2.05);
#1389=EDGE_CURVE('E798',#1052,#1249,#1388,.F.);
#1390=ORIENTED_EDGE('',*,*,#1389,.T.);
#1391=ORIENTED_EDGE('',*,*,#1250,.T.);
#1392=ORIENTED_EDGE('',*,*,#298,.F.);
#1393=EDGE_LOOP('',(#1383,#1390,#1391,#1392));
#1394=FACE_BOUND('',#1393,.T.);
#1395=ADVANCED_FACE('F899',(#1394),#1382,.F.);
#1396=CARTESIAN_POINT('',(-5.52191530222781,53.371072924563,-23.58125));
#1397=DIRECTION('',(0.,0.,1.));
#1398=DIRECTION('',(0.883135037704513,0.469118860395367,0.));
#1399=AXIS2_PLACEMENT_3D('',#1396,#1397,#1398);
#1400=CYLINDRICAL_SURFACE('',#1399,2.05);
#1401=ORIENTED_EDGE('',*,*,#1233,.T.);
#1402=CARTESIAN_POINT('',(-5.52191530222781,53.371072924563,-23.58125));
#1403=DIRECTION('',(0.,0.,-1.));
#1404=DIRECTION('',(-0.883135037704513,-0.469118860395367,0.));
#1405=AXIS2_PLACEMENT_3D('',#1402,#1403,#1404);
#1406=CIRCLE('',#1405,2.05);
#1407=EDGE_CURVE('E796',#1226,#1106,#1406,.F.);
#1408=ORIENTED_EDGE('',*,*,#1407,.T.);
#1409=ORIENTED_EDGE('',*,*,#1107,.T.);
#1410=ORIENTED_EDGE('',*,*,#333,.F.);
#1411=EDGE_LOOP('',(#1401,#1408,#1409,#1410));
#1412=FACE_BOUND('',#1411,.T.);
#1413=ADVANCED_FACE('F889',(#1412),#1400,.F.);
#1414=CARTESIAN_POINT('',(-7.9759505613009,57.9908925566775,-23.58125));
#1415=DIRECTION('',(0.,0.,-1.));
#1416=DIRECTION('',(-0.883135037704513,-0.469118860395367,0.));
#1417=AXIS2_PLACEMENT_3D('',#1414,#1415,#1416);
#1418=CYLINDRICAL_SURFACE('',#1417,2.05);
#1419=ORIENTED_EDGE('',*,*,#1121,.T.);
#1420=CARTESIAN_POINT('',(-7.9759505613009,57.9908925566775,-23.58125));
#1421=DIRECTION('',(0.,0.,-1.));
#1422=DIRECTION('',(-0.883135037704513,-0.469118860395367,0.));
#1423=AXIS2_PLACEMENT_3D('',#1420,#1421,#1422);
#1424=CIRCLE('',#1423,2.05);
#1425=EDGE_CURVE('E794',#1114,#1137,#1424,.F.);
#1426=ORIENTED_EDGE('',*,*,#1425,.T.);
#1427=ORIENTED_EDGE('',*,*,#1138,.T.);
#1428=ORIENTED_EDGE('',*,*,#350,.F.);
#1429=EDGE_LOOP('',(#1419,#1426,#1427,#1428));
#1430=FACE_BOUND('',#1429,.T.);
#1431=ADVANCED_FACE('F373',(#1430),#1418,.F.);
#1432=CARTESIAN_POINT('',(0.,32.051109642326,-23.58125));
#1433=DIRECTION('',(0.,0.,-1.));
#1434=DIRECTION('',(-0.883135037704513,-0.469118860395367,0.));
#1435=AXIS2_PLACEMENT_3D('',#1432,#1433,#1434);
#1436=PLANE('',#1435);
#1437=ORIENTED_EDGE('',*,*,#1146,.F.);
#1438=ORIENTED_EDGE('',*,*,#1425,.F.);
#1439=ORIENTED_EDGE('',*,*,#1115,.F.);
#1440=ORIENTED_EDGE('',*,*,#1407,.F.);
#1441=ORIENTED_EDGE('',*,*,#1227,.F.);
#1442=ORIENTED_EDGE('',*,*,#1084,.F.);
#1443=ORIENTED_EDGE('',*,*,#1257,.F.);
#1444=ORIENTED_EDGE('',*,*,#1389,.F.);
#1445=ORIENTED_EDGE('',*,*,#1053,.F.);
#1446=ORIENTED_EDGE('',*,*,#1371,.F.);
#1447=ORIENTED_EDGE('',*,*,#1022,.F.);
#1448=ORIENTED_EDGE('',*,*,#1353,.F.);
#1449=ORIENTED_EDGE('',*,*,#976,.F.);
#1450=ORIENTED_EDGE('',*,*,#1335,.F.);
#1451=ORIENTED_EDGE('',*,*,#1277,.F.);
#1452=ORIENTED_EDGE('',*,*,#937,.F.);
#1453=ORIENTED_EDGE('',*,*,#1207,.F.);
#1454=ORIENTED_EDGE('',*,*,#1317,.F.);
#1455=ORIENTED_EDGE('',*,*,#1177,.F.);
#1456=ORIENTED_EDGE('',*,*,#1299,.F.);
#1457=EDGE_LOOP('',(#1437,#1438,#1439,#1440,#1441,#1442,#1443,#1444,#1445,#1446,#1447,#1448,
#1449,#1450,#1451,#1452,#1453,#1454,#1455,#1456));
#1458=FACE_BOUND('',#1457,.T.);
#1459=ADVANCED_FACE('F364',(#1458),#1436,.T.);
#1460=CARTESIAN_POINT('',(2.8972360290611,7.03900367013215,-22.1));
#1461=DIRECTION('',(0.,0.,-1.));
#1462=DIRECTION('',(-1.,0.,0.));
#1463=AXIS2_PLACEMENT_3D('',#1460,#1461,#1462);
#1464=PLANE('',#1463);
#1465=ORIENTED_EDGE('',*,*,#51,.T.);
#1466=DIRECTION('',(0.883135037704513,0.469118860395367,0.));
#1467=VECTOR('',#1466,1.);
#1468=CARTESIAN_POINT('',(2.31668548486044,8.13191331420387,-22.1));
#1469=LINE('',#1468,#1467);
#1470=CARTESIAN_POINT('',(2.31668548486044,8.13191331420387,-22.1));
#1471=VERTEX_POINT('',#1470);
#1472=EDGE_CURVE('E736',#41,#1471,#1469,.T.);
#1473=ORIENTED_EDGE('',*,*,#1472,.T.);
#1474=CARTESIAN_POINT('',(2.8972360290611,7.03900367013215,-22.1));
#1475=DIRECTION('',(0.,0.,-1.));
#1476=DIRECTION('',(-1.,0.,0.));
#1477=AXIS2_PLACEMENT_3D('',#1474,#1475,#1476);
#1478=CIRCLE('',#1477,1.23753400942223);
#1479=CARTESIAN_POINT('',(3.47778657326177,5.94609402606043,-22.1));
#1480=VERTEX_POINT('',#1479);
#1481=EDGE_CURVE('E725',#1471,#1480,#1478,.T.);
#1482=ORIENTED_EDGE('',*,*,#1481,.T.);
#1483=DIRECTION('',(-0.883135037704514,-0.469118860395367,0.));
#1484=VECTOR('',#1483,1.);
#1485=CARTESIAN_POINT('',(3.47778657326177,5.94609402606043,-22.1));
#1486=LINE('',#1485,#1484);
#1487=EDGE_CURVE('E728',#1480,#50,#1486,.T.);
#1488=ORIENTED_EDGE('',*,*,#1487,.T.);
#1489=EDGE_LOOP('',(#1465,#1473,#1482,#1488));
#1490=FACE_BOUND('',#1489,.T.);
#1491=ADVANCED_FACE('F361',(#1490),#1464,.T.);
#1492=CARTESIAN_POINT('',(2.19355773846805,8.36370622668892,-25.1));
#1493=DIRECTION('',(-0.467333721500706,0.87977444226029,0.0871557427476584));
#1494=DIRECTION('',(-0.883135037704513,-0.469118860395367,0.));
#1495=AXIS2_PLACEMENT_3D('',#1492,#1493,#1494);
#1496=PLANE('',#1495);
#1497=ORIENTED_EDGE('',*,*,#230,.T.);
#1498=DIRECTION('',(-0.0408864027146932,0.0769702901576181,-0.996194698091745));
#1499=VECTOR('',#1498,1.);
#1500=CARTESIAN_POINT('',(2.19355773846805,8.36370622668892,-25.1));
#1501=LINE('',#1500,#1499);
#1502=EDGE_CURVE('E733',#1471,#223,#1501,.T.);
#1503=ORIENTED_EDGE('',*,*,#1502,.F.);
#1504=ORIENTED_EDGE('',*,*,#1472,.F.);
#1505=ORIENTED_EDGE('',*,*,#42,.F.);
#1506=EDGE_LOOP('',(#1497,#1503,#1504,#1505));
#1507=FACE_BOUND('',#1506,.T.);
#1508=ADVANCED_FACE('F363',(#1507),#1496,.F.);
#1509=CARTESIAN_POINT('',(3.60091431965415,5.71430111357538,-25.1));
#1510=DIRECTION('',(0.467333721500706,-0.87977444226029,0.0871557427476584));
#1511=DIRECTION('',(0.883135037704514,0.469118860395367,0.));
#1512=AXIS2_PLACEMENT_3D('',#1509,#1510,#1511);
#1513=PLANE('',#1512);
#1514=ORIENTED_EDGE('',*,*,#1487,.F.);
#1515=DIRECTION('',(0.0408864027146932,-0.0769702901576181,-0.996194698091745));
#1516=VECTOR('',#1515,1.);
#1517=CARTESIAN_POINT('',(3.60091431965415,5.71430111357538,-25.1));
#1518=LINE('',#1517,#1516);
#1519=EDGE_CURVE('E735',#1480,#238,#1518,.T.);
#1520=ORIENTED_EDGE('',*,*,#1519,.T.);
#1521=ORIENTED_EDGE('',*,*,#239,.T.);
#1522=ORIENTED_EDGE('',*,*,#58,.F.);
#1523=EDGE_LOOP('',(#1514,#1520,#1521,#1522));
#1524=FACE_BOUND('',#1523,.T.);
#1525=ADVANCED_FACE('F370',(#1524),#1513,.F.);
#1526=CARTESIAN_POINT('',(2.8972360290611,7.03900367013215,-25.1));
#1527=DIRECTION('',(0.,0.,-1.));
#1528=DIRECTION('',(-1.,0.,0.));
#1529=AXIS2_PLACEMENT_3D('',#1526,#1527,#1528);
#1530=CONICAL_SURFACE('',#1529,1.5,0.0872664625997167);
#1531=ORIENTED_EDGE('',*,*,#224,.T.);
#1532=CARTESIAN_POINT('',(3.91162907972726,8.14401915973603,-25.1002000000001));
#1533=CARTESIAN_POINT('',(3.90706996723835,8.13829958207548,-25.0167999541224));
#1534=CARTESIAN_POINT('',(3.9025106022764,8.132579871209,-24.9333999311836));
#1535=CARTESIAN_POINT('',(3.89339136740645,8.12114018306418,-24.7665999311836));
#1536=CARTESIAN_POINT('',(3.88883149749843,8.11542020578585,-24.6831999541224));
#1537=CARTESIAN_POINT('',(3.88427137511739,8.10970009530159,-24.5998));
#1538=B_SPLINE_CURVE_WITH_KNOTS('',3,(#1532,#1533,#1534,#1535,#1536,#1537),.UNSPECIFIED.,.F.,
.F.,(4,2,4),(0.,0.251160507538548,0.502321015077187),.UNSPECIFIED.);
#1539=CARTESIAN_POINT('',(3.88428231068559,8.10971381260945,-24.6));
#1540=VERTEX_POINT('',#1539);
#1541=EDGE_CURVE('E11',#214,#1540,#1538,.T.);
#1542=ORIENTED_EDGE('',*,*,#1541,.T.);
#1543=CARTESIAN_POINT('',(2.8972360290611,7.03900367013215,-24.6));
#1544=DIRECTION('',(0.,0.,1.));
#1545=DIRECTION('',(1.,0.,0.));
#1546=AXIS2_PLACEMENT_3D('',#1543,#1544,#1545);
#1547=CIRCLE('',#1546,1.45625566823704);
#1548=CARTESIAN_POINT('',(4.33701917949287,7.2574185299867,-24.6));
#1549=VERTEX_POINT('',#1548);
#1550=EDGE_CURVE('E343',#1540,#1549,#1547,.F.);
#1551=ORIENTED_EDGE('',*,*,#1550,.T.);
#1552=CARTESIAN_POINT('',(4.33700169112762,7.25741714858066,-24.5998));
#1553=CARTESIAN_POINT('',(4.34429432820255,7.25799319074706,-24.6831999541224));
#1554=CARTESIAN_POINT('',(4.35158671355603,7.25856909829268,-24.7665999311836));
#1555=CARTESIAN_POINT('',(4.36617098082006,7.25972064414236,-24.9333999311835));
#1556=CARTESIAN_POINT('',(4.3734628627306,7.26029628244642,-25.0167999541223));
#1557=CARTESIAN_POINT('',(4.38075449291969,7.2608717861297,-25.1002));
#1558=B_SPLINE_CURVE_WITH_KNOTS('',3,(#1552,#1553,#1554,#1555,#1556,#1557),.UNSPECIFIED.,.F.,
.F.,(4,2,4),(0.,0.251160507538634,0.502321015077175),.UNSPECIFIED.);
#1559=EDGE_CURVE('E47',#1549,#242,#1558,.T.);
#1560=ORIENTED_EDGE('',*,*,#1559,.T.);
#1561=ORIENTED_EDGE('',*,*,#243,.T.);
#1562=ORIENTED_EDGE('',*,*,#1519,.F.);
#1563=ORIENTED_EDGE('',*,*,#1481,.F.);
#1564=ORIENTED_EDGE('',*,*,#1502,.T.);
#1565=EDGE_LOOP('',(#1531,#1542,#1551,#1560,#1561,#1562,#1563,#1564));
#1566=FACE_BOUND('',#1565,.T.);
#1567=ADVANCED_FACE('F349',(#1566),#1530,.F.);
#1568=CARTESIAN_POINT('',(4.8705141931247,8.65336833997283,-25.1));
#1569=DIRECTION('',(-0.468833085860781,0.882597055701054,0.034899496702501));
#1570=DIRECTION('',(-0.883135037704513,-0.469118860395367,0.));
#1571=AXIS2_PLACEMENT_3D('',#1568,#1569,#1570);
#1572=PLANE('',#1571);
#1573=ORIENTED_EDGE('',*,*,#959,.T.);
#1574=DIRECTION('',(0.883135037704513,0.469118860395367,0.));
#1575=VECTOR('',#1574,1.);
#1576=CARTESIAN_POINT('',(4.87870518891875,8.63794846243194,-24.6));
#1577=LINE('',#1576,#1575);
#1578=EDGE_CURVE('E832',#1540,#958,#1577,.T.);
#1579=ORIENTED_EDGE('',*,*,#1578,.F.);
#1580=ORIENTED_EDGE('',*,*,#1541,.F.);
#1581=ORIENTED_EDGE('',*,*,#215,.T.);
#1582=EDGE_LOOP('',(#1573,#1579,#1580,#1581));
#1583=FACE_BOUND('',#1582,.T.);
#1584=ADVANCED_FACE('F357',(#1583),#1572,.F.);
#1585=CARTESIAN_POINT('',(5.33963305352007,7.77023330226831,-25.1));
#1586=DIRECTION('',(0.468833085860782,-0.882597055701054,0.034899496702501));
#1587=DIRECTION('',(0.883135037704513,0.469118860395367,0.));
#1588=AXIS2_PLACEMENT_3D('',#1585,#1586,#1587);
#1589=PLANE('',#1588);
#1590=ORIENTED_EDGE('',*,*,#991,.T.);
#1591=ORIENTED_EDGE('',*,*,#251,.T.);
#1592=ORIENTED_EDGE('',*,*,#1559,.F.);
#1593=DIRECTION('',(-0.883135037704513,-0.469118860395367,0.));
#1594=VECTOR('',#1593,1.);
#1595=CARTESIAN_POINT('',(5.33144205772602,7.78565317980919,-24.6));
#1596=LINE('',#1595,#1594);
#1597=EDGE_CURVE('E54',#990,#1549,#1596,.T.);
#1598=ORIENTED_EDGE('',*,*,#1597,.F.);
#1599=EDGE_LOOP('',(#1590,#1591,#1592,#1598));
#1600=FACE_BOUND('',#1599,.T.);
#1601=ADVANCED_FACE('F310',(#1600),#1589,.F.);
#1602=CARTESIAN_POINT('',(0.,0.,-24.6));
#1603=DIRECTION('',(0.,0.,1.));
#1604=DIRECTION('',(1.,0.,0.));
#1605=AXIS2_PLACEMENT_3D('',#1602,#1603,#1604);
#1606=PLANE('',#1605);
#1607=ORIENTED_EDGE('',*,*,#997,.T.);
#1608=ORIENTED_EDGE('',*,*,#1597,.T.);
#1609=ORIENTED_EDGE('',*,*,#1550,.F.);
#1610=ORIENTED_EDGE('',*,*,#1578,.T.);
#1611=EDGE_LOOP('',(#1607,#1608,#1609,#1610));
#1612=FACE_BOUND('',#1611,.T.);
#1613=ADVANCED_FACE('F356',(#1612),#1606,.F.);
#1614=CLOSED_SHELL('',(#73,#113,#153,#193,#468,#499,#539,#579,#652,#710,#768,#780,#792,#804,
#816,#828,#840,#852,#864,#884,#904,#916,#947,#1001,#1032,#1063,#1094,#1125,#1156,#1187,#1212,
#1237,#1262,#1287,#1305,#1323,#1341,#1359,#1377,#1395,#1413,#1431,#1459,#1491,#1508,#1525,#1567,
#1584,#1601,#1613));
#1615=MANIFOLD_SOLID_BREP('B2',#1614);
#1616=ADVANCED_BREP_SHAPE_REPRESENTATION('',(#18,#1615),#14);
#1617=SHAPE_DEFINITION_REPRESENTATION(#9,#1616);
ENDSEC;
END-ISO-10303-21;
